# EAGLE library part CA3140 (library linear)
OP AMP

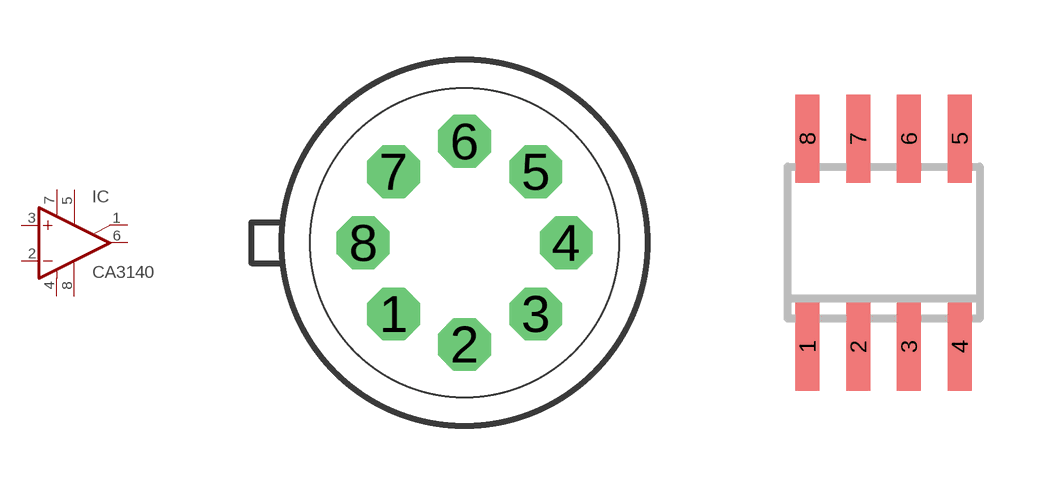
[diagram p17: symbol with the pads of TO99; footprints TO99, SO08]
Designator prefix IC

## CA3140T  [TO99]
1  ON/CMP  pas
2  -IN  in
3  +IN  in
4  V-  pwr
5  ON  pas
6  OUT  out
7  V+  pwr
8  CMP  pas

## CA3140D  [SO08]
Pads as for TO99

## CA3140N  [DIL08]
Pads as for TO99

## Footprint TO99 (pad centres in mm)
Metal Can Package
drill 0.813 octagon: 1 -1.778,-1.778; 2 0,-2.54; 3 1.778,-1.778; 4 2.54,0; 5 1.778,1.778; 6 0,2.54; 7 -1.778,1.778; 8 -2.54,0

## Footprint SO08 (pad centres in mm)
Small Outline Package 8 NS Package M08A
smd 0.6 x 2.2: 1 -1.905,-2.6; 2 -0.635,-2.6; 3 0.635,-2.6; 4 1.905,-2.6; 5 1.905,2.6; 6 0.635,2.6; 7 -0.635,2.6; 8 -1.905,2.6

## Footprint DIL08 (pad centres in mm)
Dual In Line Package
drill 0.813 pad 1.27 round: 1 -3.81,-3.81; 2 -1.27,-3.81; 3 1.27,-3.81; 4 3.81,-3.81; 5 3.81,3.81; 6 1.27,3.81; 7 -1.27,3.81; 8 -3.81,3.81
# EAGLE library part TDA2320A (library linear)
Power OP AMP

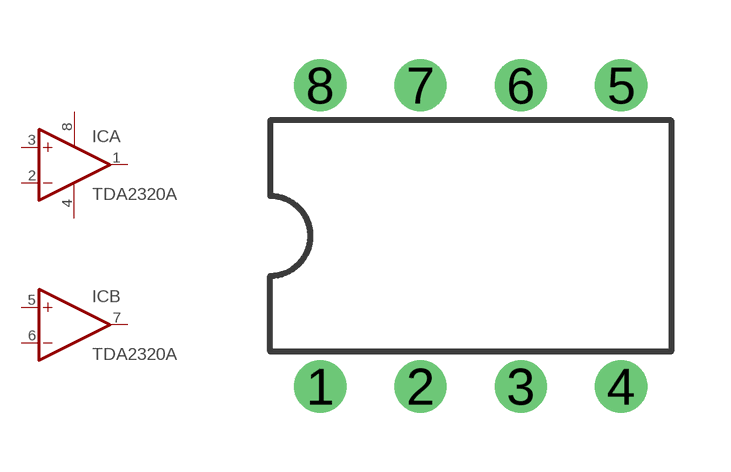
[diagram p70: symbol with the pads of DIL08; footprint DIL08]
Designator prefix IC; gates A=OPAMP B=OPAMP P=PWR+-

## TDA2320AP  [DIL08]
1  A:OUT  out
2  A:-IN  in
3  A:+IN  in
4  P:V-  pwr
5  B:+IN  in
6  B:-IN  in
7  B:OUT  out
8  P:V+  pwr

## Footprint DIL08 (pad centres in mm)
Dual In Line Package
drill 0.813 pad 1.27 round: 1 -3.81,-3.81; 2 -1.27,-3.81; 3 1.27,-3.81; 4 3.81,-3.81; 5 3.81,3.81; 6 1.27,3.81; 7 -1.27,3.81; 8 -3.81,3.81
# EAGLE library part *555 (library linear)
TIMER

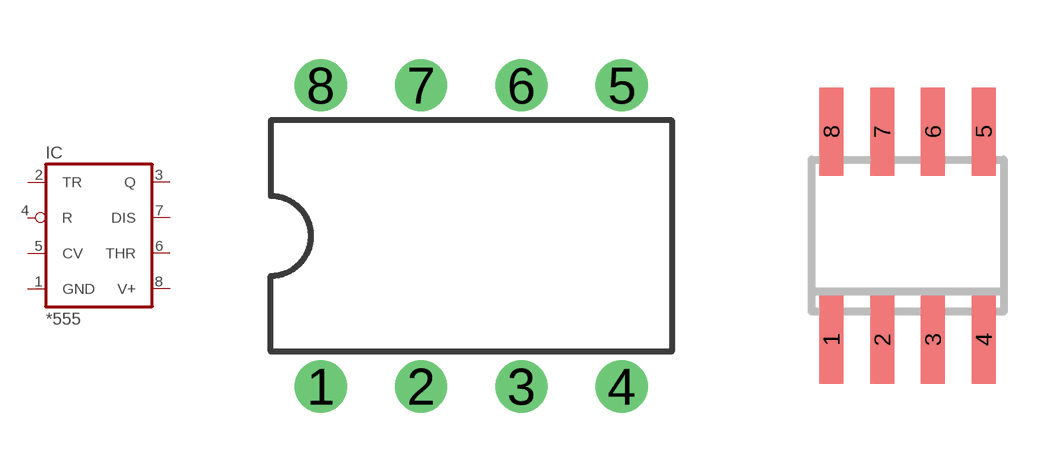
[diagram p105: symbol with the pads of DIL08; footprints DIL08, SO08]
Designator prefix IC

## LM555N, NE555N, SE555N, UA555N  [DIL08]
1  GND  pwr
2  TR  in
3  Q  out
4  R  in
5  CV  in
6  THR  in
7  DIS  in
8  V+  pwr

## LM555D, NE555D, SE555D, UA555D  [SO08]
Pads as for DIL08

## Footprint DIL08 (pad centres in mm)
Dual In Line Package
drill 0.813 pad 1.27 round: 1 -3.81,-3.81; 2 -1.27,-3.81; 3 1.27,-3.81; 4 3.81,-3.81; 5 3.81,3.81; 6 1.27,3.81; 7 -1.27,3.81; 8 -3.81,3.81

## Footprint SO08 (pad centres in mm)
Small Outline Package 8 NS Package M08A
smd 0.6 x 2.2: 1 -1.905,-2.6; 2 -0.635,-2.6; 3 0.635,-2.6; 4 1.905,-2.6; 5 1.905,2.6; 6 0.635,2.6; 7 -0.635,2.6; 8 -1.905,2.6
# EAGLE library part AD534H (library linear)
MULTIPLIER

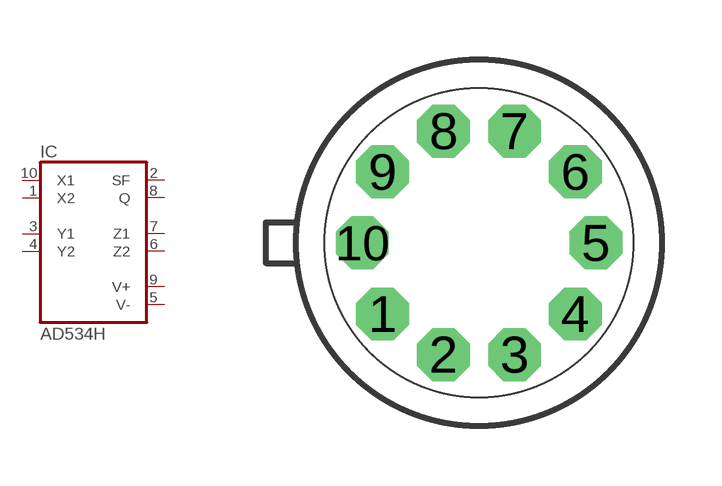
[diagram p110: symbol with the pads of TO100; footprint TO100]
Designator prefix IC

## AD534H  [TO100]
1  X2  in
2  SF  in
3  Y1  in
4  Y2  in
5  V-  pwr
6  Z2  in
7  Z1  in
8  Q  out
9  V+  pwr
10  X1  in

## Footprint TO100 (pad centres in mm)
Metal Can Package
drill 0.813 octagon: 1 -2.413,-1.778; 2 -0.889,-2.794; 3 0.889,-2.794; 4 2.413,-1.778; 5 2.921,0; 6 2.413,1.778; 7 0.889,2.794; 8 -0.889,2.794; 9 -2.413,1.778; 10 -2.921,0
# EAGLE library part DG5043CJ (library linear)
CMOS SWITCH

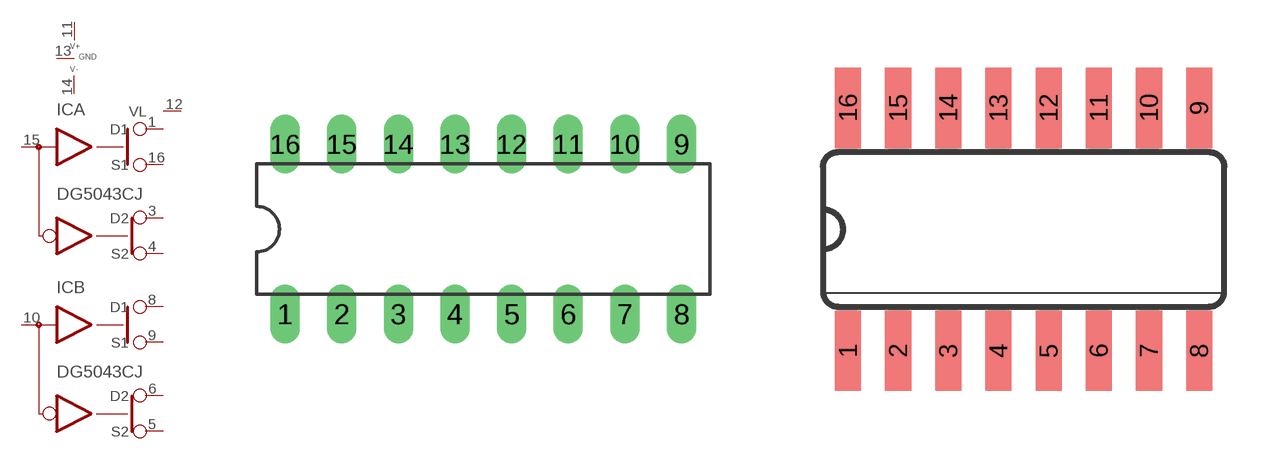
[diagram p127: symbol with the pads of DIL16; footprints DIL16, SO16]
Designator prefix IC; gates A=SWDPST B=SWDPST P=PWR+-GSS VL=VL_PIN

## DG5043CJN  [DIL16]
1  A:D1
3  A:D2
4  A:S2
5  B:S2
6  B:D2
8  B:D1
9  B:S1
10  B:IN  in
11  P:V+  pwr
12  VL:VL  in
13  P:GND  pwr
14  P:V-  pwr
15  A:IN  in
16  A:S1

## DG5043CJD  [SO16]
Pads as for DIL16

## Footprint DIL16 (pad centres in mm)
Dual In Line Package
drill 0.813 long: 1 -8.89,-3.81; 2 -6.35,-3.81; 3 -3.81,-3.81; 4 -1.27,-3.81; 5 1.27,-3.81; 6 3.81,-3.81; 7 6.35,-3.81; 8 8.89,-3.81; 9 8.89,3.81; 10 6.35,3.81; 11 3.81,3.81; 12 1.27,3.81; 13 -1.27,3.81; 14 -3.81,3.81; 15 -6.35,3.81; 16 -8.89,3.81

## Footprint SO16 (pad centres in mm)
Small Outline Package 16
smd 0.66 x 2.032: 1 -4.445,-3.073; 2 -3.175,-3.073; 3 -1.905,-3.073; 4 -0.635,-3.073; 5 0.635,-3.073; 6 1.905,-3.073; 7 3.175,-3.073; 8 4.445,-3.073; 9 4.445,3.073; 10 3.175,3.073; 11 1.905,3.073; 12 0.635,3.073; 13 -0.635,3.073; 14 -1.905,3.073; 15 -3.175,3.073; 16 -4.445,3.073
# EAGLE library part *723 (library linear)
Positive VOLTAGE REGULATOR

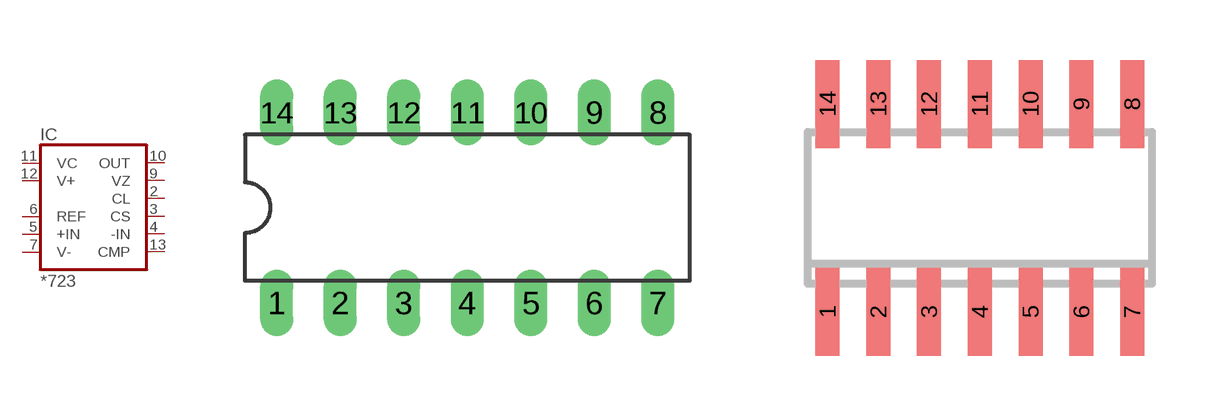
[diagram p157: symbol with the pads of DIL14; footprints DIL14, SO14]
Designator prefix IC

## LM723N, UA723N  [DIL14]
2  CL  in
3  CS  in
4  -IN  in
5  +IN  in
6  REF  out
7  V-  in
9  VZ  out
10  OUT  out
11  VC  in
12  V+  in
13  CMP  pas

## LM723D, UA723D  [SO14]
Pads as for DIL14

## Footprint DIL14 (pad centres in mm)
Dual In Line Package
drill 0.813 long: 1 -7.62,-3.81; 2 -5.08,-3.81; 3 -2.54,-3.81; 4 0,-3.81; 5 2.54,-3.81; 6 5.08,-3.81; 7 7.62,-3.81; 8 7.62,3.81; 9 5.08,3.81; 10 2.54,3.81; 11 0,3.81; 12 -2.54,3.81; 13 -5.08,3.81; 14 -7.62,3.81

## Footprint SO14 (pad centres in mm)
Small Outline Package 14
smd 0.6 x 2.2: 1 -3.81,-2.6; 2 -2.54,-2.6; 3 -1.27,-2.6; 4 0,-2.6; 5 1.27,-2.6; 6 2.54,-2.6; 7 3.81,-2.6; 8 3.81,2.6; 9 2.54,2.6; 10 1.27,2.6; 11 0,2.6; 12 -1.27,2.6; 13 -2.54,2.6; 14 -3.81,2.6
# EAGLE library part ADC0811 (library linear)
A/D CONVERTER with 10-channel multiplexer

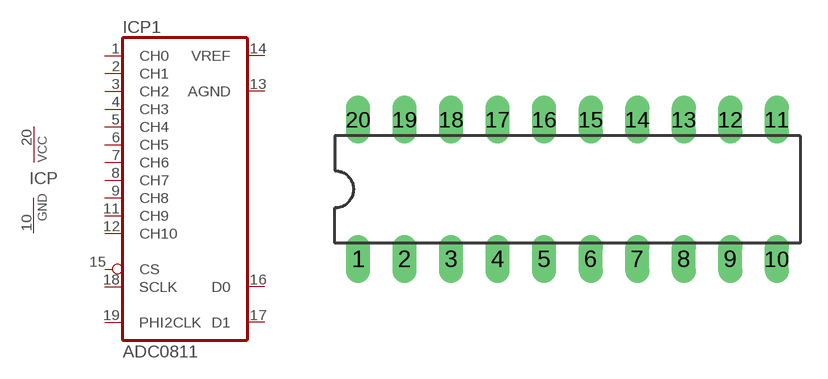
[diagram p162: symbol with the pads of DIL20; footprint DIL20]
Designator prefix IC; gates P1=ADC0811 P=PWRN

## ADC0811  [DIL20]
1  P1:CH0  in
2  P1:CH1  in
3  P1:CH2  in
4  P1:CH3  in
5  P1:CH4  in
6  P1:CH5  in
7  P1:CH6  in
8  P1:CH7  in
9  P1:CH8  in
10  P:GND  pwr
11  P1:CH9  in
12  P1:CH10  in
13  P1:AGND  in
14  P1:VREF  in
15  P1:CS  in
16  P1:D0  out
17  P1:D1  in
18  P1:SCLK  in
19  P1:PHI2CLK  in
20  P:VCC  pwr

## Footprint DIL20 (pad centres in mm)
Dual In Line Package
drill 0.813 long: 1 -11.43,-3.81; 2 -8.89,-3.81; 3 -6.35,-3.81; 4 -3.81,-3.81; 5 -1.27,-3.81; 6 1.27,-3.81; 7 3.81,-3.81; 8 6.35,-3.81; 9 8.89,-3.81; 10 11.43,-3.81; 11 11.43,3.81; 12 8.89,3.81; 13 6.35,3.81; 14 3.81,3.81; 15 1.27,3.81; 16 -1.27,3.81; 17 -3.81,3.81; 18 -6.35,3.81; 19 -8.89,3.81; 20 -11.43,3.81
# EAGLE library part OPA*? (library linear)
Ultra-Low Noise, Precision OP AMP Source: http://focus.ti.com/lit/ds/symlink/opa27.pdf http://focus.ti.com .. opa241.pdf

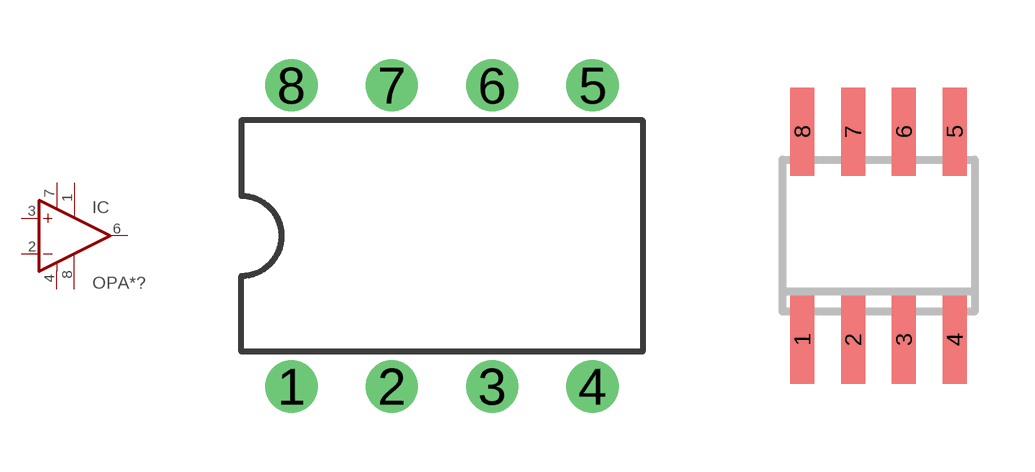
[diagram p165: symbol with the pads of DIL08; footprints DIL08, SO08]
Designator prefix IC

## OPA27GP, OPA37GP  [DIL08]
1  OFF1  pas
2  -IN  in
3  +IN  in
4  V-  pwr
6  OUT  out
7  V+  pwr
8  OFF2  pas

## OPA27U, OPA37U  [SO08]
Pads as for DIL08

## OPA241PA, OPA251PA  [DIL08]
Pads as for DIL08

## OPA241UA, OPA251UA  [SO08]
Pads as for DIL08

## Footprint DIL08 (pad centres in mm)
Dual In Line Package
drill 0.813 pad 1.27 round: 1 -3.81,-3.81; 2 -1.27,-3.81; 3 1.27,-3.81; 4 3.81,-3.81; 5 3.81,3.81; 6 1.27,3.81; 7 -1.27,3.81; 8 -3.81,3.81

## Footprint SO08 (pad centres in mm)
Small Outline Package 8 NS Package M08A
smd 0.6 x 2.2: 1 -1.905,-2.6; 2 -0.635,-2.6; 3 0.635,-2.6; 4 1.905,-2.6; 5 1.905,2.6; 6 0.635,2.6; 7 -0.635,2.6; 8 -1.905,2.6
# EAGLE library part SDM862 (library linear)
DATA ACQUSITION SYSTEM

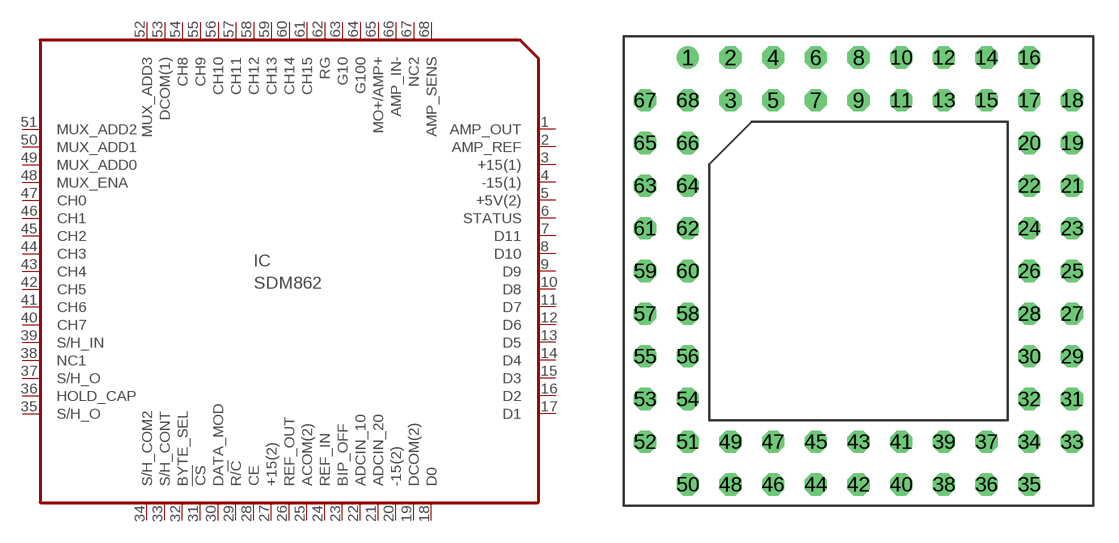
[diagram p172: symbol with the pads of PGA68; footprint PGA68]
Designator prefix IC

## SDM862  [PGA68]
1  AMP_OUT  out
2  AMP_REF  in
3  +15(1)  pwr
4  -15(1)  pwr
5  +5V(2)  pwr
6  STATUS  out
7  D11  hiz
8  D10  hiz
9  D9  hiz
10  D8  hiz
11  D7  hiz
12  D6  hiz
13  D5  hiz
14  D4  hiz
15  D3  hiz
16  D2  hiz
17  D1  hiz
18  D0  hiz
19  DCOM(2)  pwr
20  -15(2)  pwr
21  ADCIN_20  in
22  ADCIN_10  in
23  BIP_OFF  in
24  REF_IN  in
25  ACOM(2)  pwr
26  REF_OUT  out
27  +15(2)  pwr
28  CE  in
29  R/!C  in
30  DATA_MOD  in
31  !CS  in
32  BYTE_SEL  in
33  S/H_CONT  in
34  S/H_COM2
35  S/H_O  out
36  HOLD_CAP  pas
37  S/H_O  out
38  NC1  nc
39  S/H_IN  in
40  CH7  in
41  CH6  in
42  CH5  in
43  CH4  in
44  CH3  in
45  CH2  in
46  CH1  in
47  CH0  in
48  MUX_ENA  in
49  MUX_ADD0  in
50  MUX_ADD1  in
51  MUX_ADD2  in
52  MUX_ADD3  in
53  DCOM(1)  pwr
54  CH8  in
55  CH9  in
56  CH10  in
57  CH11  in
58  CH12  in
59  CH13  in
60  CH14  in
61  CH15  in
62  RG  pas
63  G10  pas
64  G100  pas
65  MO+/AMP+
66  AMP_IN-  in
67  NC2  nc
68  AMP_SENS  out

## Footprint PGA68 (pad centres in mm)
Pin Grid Array 68 lead
drill 0.813 round: 1 -10.16,12.7
drill 0.813 octagon: 2 -7.62,12.7; 3 -7.62,10.16; 4 -5.08,12.7; 5 -5.08,10.16; 6 -2.54,12.7; 7 -2.54,10.16; 8 0,12.7; 9 0,10.16; 10 2.54,12.7; 11 2.54,10.16; 12 5.08,12.7; 13 5.08,10.16; 14 7.62,12.7; 15 7.62,10.16; 16 10.16,12.7; 17 10.16,10.16; 18 12.7,10.16; 19 12.7,7.62; 20 10.16,7.62; 21 12.7,5.08; 22 10.16,5.08; 23 12.7,2.54; 24 10.16,2.54; 25 12.7,0; 26 10.16,0; 27 12.7,-2.54; 28 10.16,-2.54; 29 12.7,-5.08; 30 10.16,-5.08; 31 12.7,-7.62; 32 10.16,-7.62; 33 12.7,-10.16; 34 10.16,-10.16; 35 10.16,-12.7; 36 7.62,-12.7; 37 7.62,-10.16; 38 5.08,-12.7; 39 5.08,-10.16; 40 2.54,-12.7; 41 2.54,-10.16; 42 0,-12.7; 43 0,-10.16; 44 -2.54,-12.7; 45 -2.54,-10.16; 46 -5.08,-12.7; 47 -5.08,-10.16; 48 -7.62,-12.7; 49 -7.62,-10.16; 50 -10.16,-12.7; 51 -10.16,-10.16; 52 -12.7,-10.16; 53 -12.7,-7.62; 54 -10.16,-7.62; 55 -12.7,-5.08; 56 -10.16,-5.08; 57 -12.7,-2.54; 58 -10.16,-2.54; 59 -12.7,0; 60 -10.16,0; 61 -12.7,2.54; 62 -10.16,2.54; 63 -12.7,5.08; 64 -10.16,5.08; 65 -12.7,7.62; 66 -10.16,7.62; 67 -12.7,10.16; 68 -10.16,10.16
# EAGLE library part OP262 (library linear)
OP AMP

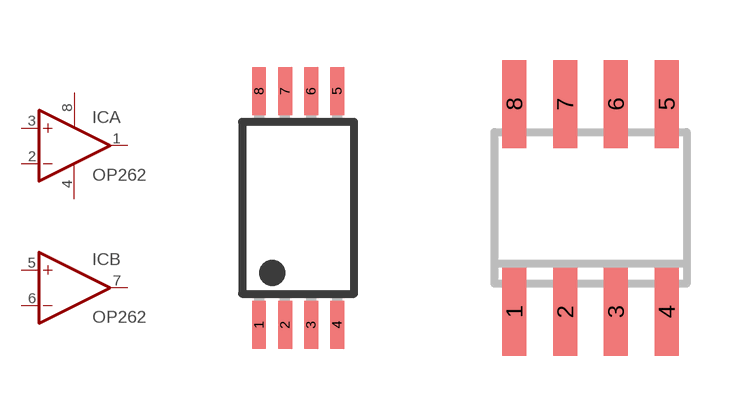
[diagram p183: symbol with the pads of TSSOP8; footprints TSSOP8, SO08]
Designator prefix IC; gates A=OPAMP B=OPAMP P=PWR+-

## OP262HRU  [TSSOP8]
1  A:OUT  out
2  A:-IN  in
3  A:+IN  in
4  P:V-  pwr
5  B:+IN  in
6  B:-IN  in
7  B:OUT  out
8  P:V+  pwr

## OP262D  [SO08]
Pads as for TSSOP8

## Footprint TSSOP8 (pad centres in mm)
Thin Shrink Small Outline Plastic 8 3 x 4.4 mm
smd 0.35 x 1.2: 1 -0.975,-2.925; 2 -0.325,-2.925; 3 0.325,-2.925; 4 0.975,-2.925; 5 0.975,2.925; 6 0.325,2.925; 7 -0.325,2.925; 8 -0.975,2.925

## Footprint SO08 (pad centres in mm)
Small Outline Package 8 NS Package M08A
smd 0.6 x 2.2: 1 -1.905,-2.6; 2 -0.635,-2.6; 3 0.635,-2.6; 4 1.905,-2.6; 5 1.905,2.6; 6 0.635,2.6; 7 -0.635,2.6; 8 -1.905,2.6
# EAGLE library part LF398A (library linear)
SAMPLE&HOLD AMPLIFIER

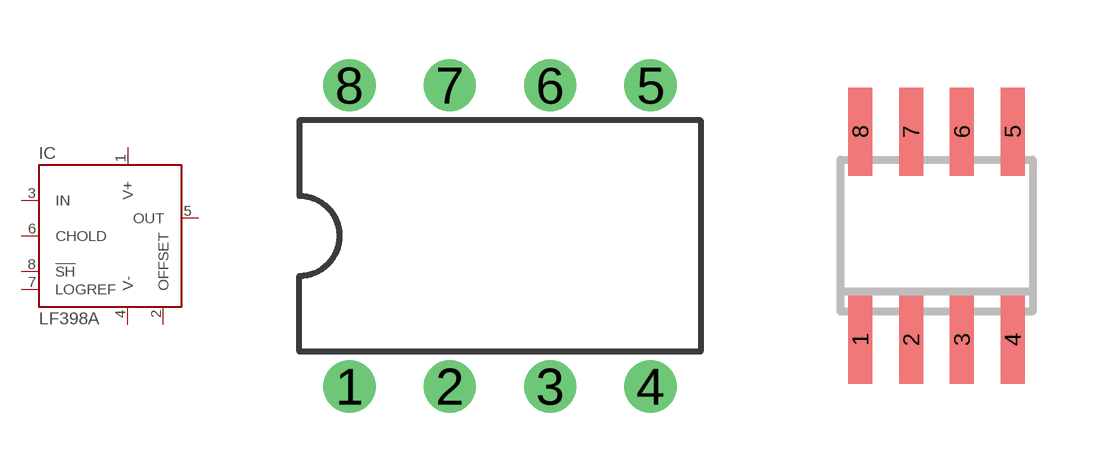
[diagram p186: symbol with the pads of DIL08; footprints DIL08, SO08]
Designator prefix IC

## LF398AN  [DIL08]
1  V+  pwr
2  OFFSET  in
3  IN  in
4  V-  pwr
5  OUT  out
6  CHOLD  pas
7  LOGREF  pwr
8  !SH  in

## LF398AD  [SO08]
Pads as for DIL08

## Footprint DIL08 (pad centres in mm)
Dual In Line Package
drill 0.813 pad 1.27 round: 1 -3.81,-3.81; 2 -1.27,-3.81; 3 1.27,-3.81; 4 3.81,-3.81; 5 3.81,3.81; 6 1.27,3.81; 7 -1.27,3.81; 8 -3.81,3.81

## Footprint SO08 (pad centres in mm)
Small Outline Package 8 NS Package M08A
smd 0.6 x 2.2: 1 -1.905,-2.6; 2 -0.635,-2.6; 3 0.635,-2.6; 4 1.905,-2.6; 5 1.905,2.6; 6 0.635,2.6; 7 -0.635,2.6; 8 -1.905,2.6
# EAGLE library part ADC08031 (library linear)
A/D CONVERTER

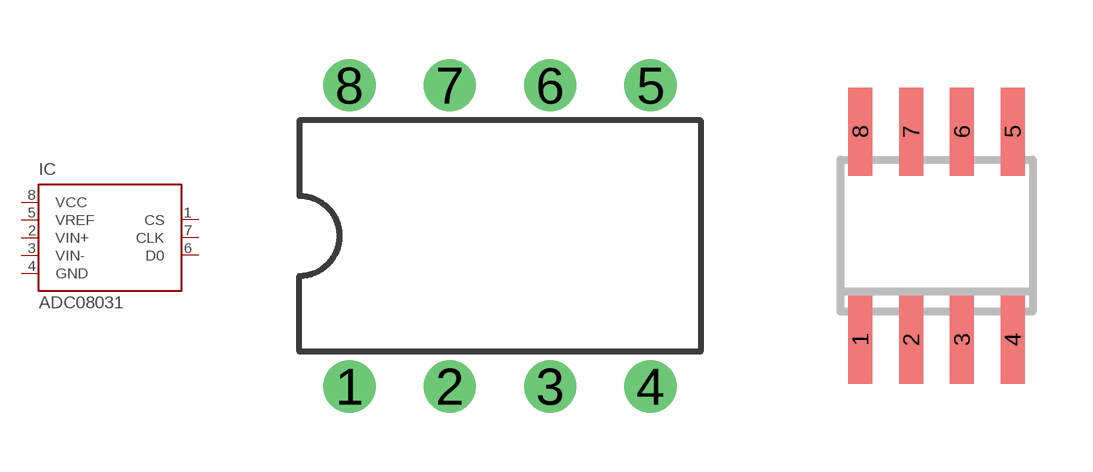
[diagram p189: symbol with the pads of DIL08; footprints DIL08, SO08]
Designator prefix IC

## ADC08031N  [DIL08]
1  CS  in
2  VIN+  in
3  VIN-  in
4  GND  pwr
5  VREF  in
6  D0  hiz
7  CLK  in
8  VCC  pwr

## ADC08031D  [SO08]
Pads as for DIL08

## Footprint DIL08 (pad centres in mm)
Dual In Line Package
drill 0.813 pad 1.27 round: 1 -3.81,-3.81; 2 -1.27,-3.81; 3 1.27,-3.81; 4 3.81,-3.81; 5 3.81,3.81; 6 1.27,3.81; 7 -1.27,3.81; 8 -3.81,3.81

## Footprint SO08 (pad centres in mm)
Small Outline Package 8 NS Package M08A
smd 0.6 x 2.2: 1 -1.905,-2.6; 2 -0.635,-2.6; 3 0.635,-2.6; 4 1.905,-2.6; 5 1.905,2.6; 6 0.635,2.6; 7 -0.635,2.6; 8 -1.905,2.6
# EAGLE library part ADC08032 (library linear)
A/D CONVERTER

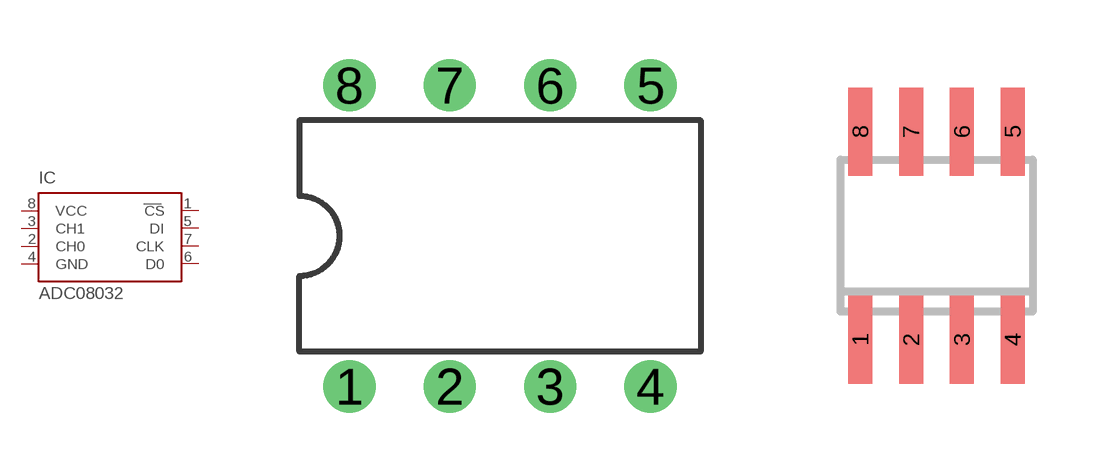
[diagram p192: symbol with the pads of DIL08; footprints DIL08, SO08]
Designator prefix IC

## ADC08032N  [DIL08]
1  CS  in
2  CH0  in
3  CH1  in
4  GND  pwr
5  DI  in
6  D0  hiz
7  CLK  in
8  VCC  pwr

## ADC08032D  [SO08]
Pads as for DIL08

## ADC08032S  [SO14W]
1  CS  in
3  CH0  in
5  CH1  in
7  GND  pwr
8  DI  in
10  D0  hiz
12  CLK  in
14  VCC  pwr

## Footprint DIL08 (pad centres in mm)
Dual In Line Package
drill 0.813 pad 1.27 round: 1 -3.81,-3.81; 2 -1.27,-3.81; 3 1.27,-3.81; 4 3.81,-3.81; 5 3.81,3.81; 6 1.27,3.81; 7 -1.27,3.81; 8 -3.81,3.81

## Footprint SO08 (pad centres in mm)
Small Outline Package 8 NS Package M08A
smd 0.6 x 2.2: 1 -1.905,-2.6; 2 -0.635,-2.6; 3 0.635,-2.6; 4 1.905,-2.6; 5 1.905,2.6; 6 0.635,2.6; 7 -0.635,2.6; 8 -1.905,2.6

## Footprint SO14W (pad centres in mm)
Small Outline Package 14 wide
smd 0.6 x 2.2: 1 -3.81,-4.6; 2 -2.54,-4.6; 3 -1.27,-4.6; 4 0,-4.6; 5 1.27,-4.6; 6 2.54,-4.6; 7 3.81,-4.6; 8 3.81,4.6; 9 2.54,4.6; 10 1.27,4.6; 11 0,4.6; 12 -1.27,4.6; 13 -2.54,4.6; 14 -3.81,4.6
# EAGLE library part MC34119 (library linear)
Low Power Audio Amplifier Motorola

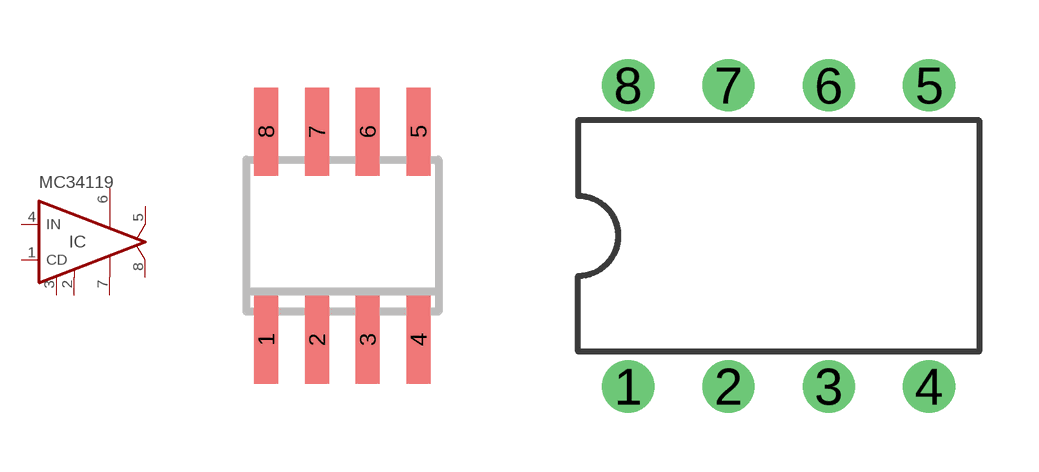
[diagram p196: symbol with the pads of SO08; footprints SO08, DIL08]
Designator prefix IC

## MC34119D  [SO08]
1  CD  pas
2  FC2  pas
3  FC1  pas
4  IN  in
5  VO1  out
6  VCC  pwr
7  GND  pwr
8  VO2  out

## MC34119P  [DIL08]
Pads as for SO08

## MC34119DTB  [TSSOP8]
Pads as for SO08

## Footprint SO08 (pad centres in mm)
Small Outline Package 8 NS Package M08A
smd 0.6 x 2.2: 1 -1.905,-2.6; 2 -0.635,-2.6; 3 0.635,-2.6; 4 1.905,-2.6; 5 1.905,2.6; 6 0.635,2.6; 7 -0.635,2.6; 8 -1.905,2.6

## Footprint DIL08 (pad centres in mm)
Dual In Line Package
drill 0.813 pad 1.27 round: 1 -3.81,-3.81; 2 -1.27,-3.81; 3 1.27,-3.81; 4 3.81,-3.81; 5 3.81,3.81; 6 1.27,3.81; 7 -1.27,3.81; 8 -3.81,3.81

## Footprint TSSOP8 (pad centres in mm)
Thin Shrink Small Outline Plastic 8 3 x 4.4 mm
smd 0.35 x 1.2: 1 -0.975,-2.925; 2 -0.325,-2.925; 3 0.325,-2.925; 4 0.975,-2.925; 5 0.975,2.925; 6 0.325,2.925; 7 -0.325,2.925; 8 -0.975,2.925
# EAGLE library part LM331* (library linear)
Simple Stand-Alone Voltage-to-Frequency Converter LM231 with ±0.03% Typical Linearity (f = 10 Hz to 11 kHz)

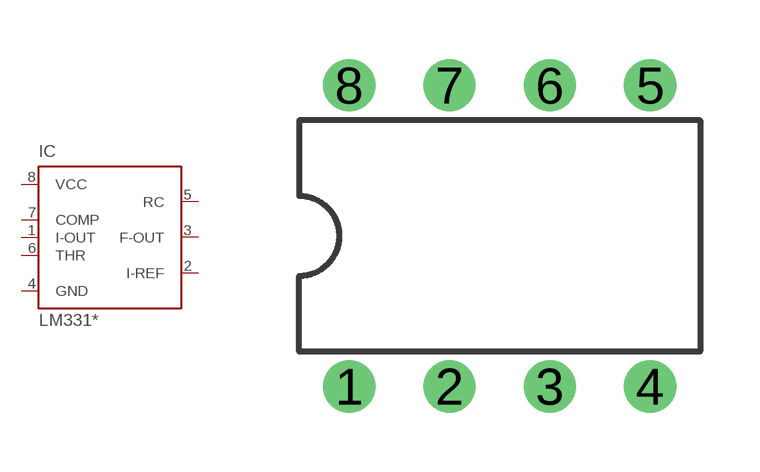
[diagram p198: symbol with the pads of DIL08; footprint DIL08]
Designator prefix IC

## LM331N, LM331AN  [DIL08]
1  I-OUT  out
2  I-REF  pas
3  F-OUT  oc
4  GND  pwr
5  RC  pas
6  THR  in
7  COMP  in
8  VCC  pwr

## Footprint DIL08 (pad centres in mm)
Dual In Line Package
drill 0.813 pad 1.27 round: 1 -3.81,-3.81; 2 -1.27,-3.81; 3 1.27,-3.81; 4 3.81,-3.81; 5 3.81,3.81; 6 1.27,3.81; 7 -1.27,3.81; 8 -3.81,3.81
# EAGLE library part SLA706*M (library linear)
UNIPOLAR STEPPER-MOTOR TRANSLATOR/DRIVERS Source: www.allegromicro.com .. 97060.pdf

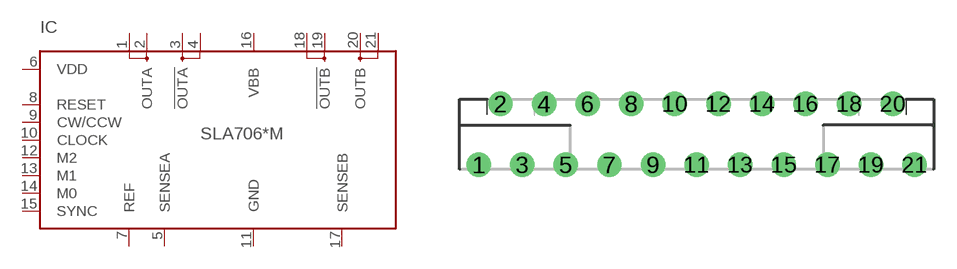
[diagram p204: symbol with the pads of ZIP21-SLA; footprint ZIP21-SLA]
Designator prefix IC

## SLA7060M, SLA7061M, SLA7062M  [ZIP21-SLA]
1  OUTA  pas
2  OUTA  out
3  !OUTA  out
4  !OUTA  pas
5  SENSEA  in
6  VDD  pwr
7  REF  in
8  RESET  in
9  CW/CCW  in
10  CLOCK  in
11  GND  pwr
12  M2  in
13  M1  in
14  M0  in
15  SYNC  in
16  VBB  pwr
17  SENSEB  in
18  !OUTB  pas
19  !OUTB  out
20  OUTB  out
21  OUTB  pas

## Footprint ZIP21-SLA (pad centres in mm)
Small molded power package ZIP-type 21-pin SLA package Source: www.allegromicro.com .. 97060.pdf
drill 0.8 pad 1.6 round: 1 -14.3,-2; 2 -12.87,2; 3 -11.44,-2; 4 -10.01,2; 5 -8.58,-2; 6 -7.15,2; 7 -5.72,-2; 8 -4.29,2; 9 -2.86,-2; 10 -1.43,2; 11 0,-2; 12 1.43,2; 13 2.86,-2; 14 4.29,2; 15 5.72,-2; 16 7.15,2; 17 8.58,-2; 18 10.01,2; 19 11.44,-2; 20 12.87,2; 21 14.3,-2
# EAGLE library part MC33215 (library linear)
Telefon Line Interface and Speakerphone Circuit Source: www.motorola.com .. MC33215.pdf

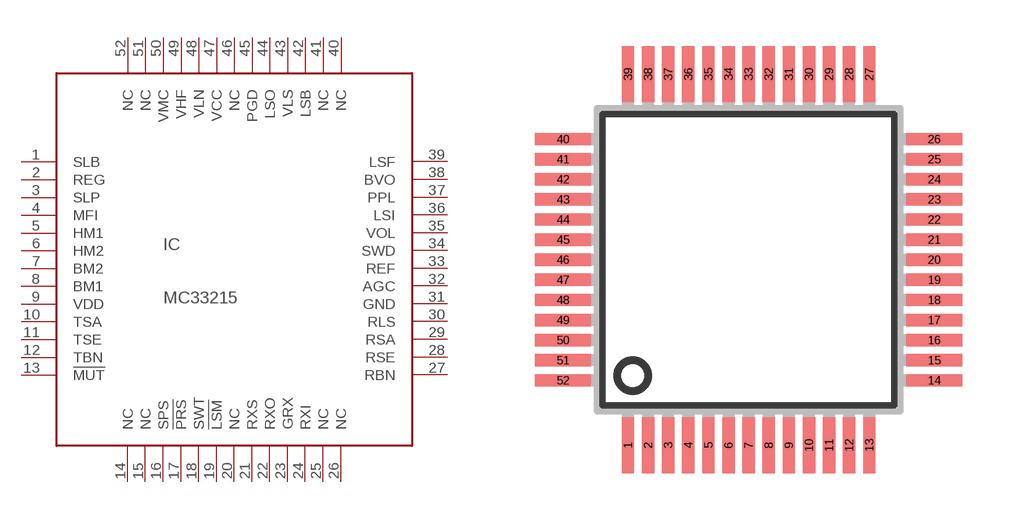
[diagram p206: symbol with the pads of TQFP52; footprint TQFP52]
Designator prefix IC

## MC33215FB  [TQFP52]
1  SLB  in
2  REG  in
3  SLP  in
4  MFI  in
5  HM1  in
6  HM2  in
7  BM2  in
8  BM1  in
9  VDD  in
10  TSA  in
11  TSE  in
12  TBN  in
13  !MUT  in
14  NC  in
15  NC  in
16  SPS  in
17  !PRS  in
18  SWT  in
19  !LSM  in
20  NC  in
21  RXS  in
22  RXO  in
23  GRX  in
24  RXI  in
25  NC  in
26  NC  in
27  RBN  in
28  RSE  in
29  RSA  in
30  RLS  in
31  GND  in
32  AGC  in
33  REF  in
34  SWD  in
35  VOL  in
36  LSI  in
37  PPL  in
38  BVO  in
39  LSF  in
40  NC  in
41  NC  in
42  LSB  in
43  VLS  in
44  LSO  in
45  PGD  in
46  NC  in
47  VCC  in
48  VLN  in
49  VHF  in
50  VMC  in
51  NC  in
52  NC  in

## Footprint TQFP52 (pad centres in mm)
TQFP-52 PLASTIC PACKAGE CASE 848B-04 Source: www.motorola.com .. MC33215.pdf
smd 0.4 x 1.8: 1 -3.9,-6; 2 -3.25,-6; 3 -2.6,-6; 4 -1.95,-6; 5 -1.3,-6; 6 -0.65,-6; 7 0,-6; 8 0.65,-6; 9 1.3,-6; 10 1.95,-6; 11 2.6,-6; 12 3.25,-6; 13 3.9,-6; 27 3.9,6; 28 3.25,6; 29 2.6,6; 30 1.95,6; 31 1.3,6; 32 0.65,6; 33 0,6; 34 -0.65,6; 35 -1.3,6; 36 -1.95,6; 37 -2.6,6; 38 -3.25,6; 39 -3.9,6
smd 1.8 x 0.4: 14 6,-3.9; 15 6,-3.25; 16 6,-2.6; 17 6,-1.95; 18 6,-1.3; 19 6,-0.65; 20 6,0; 21 6,0.65; 22 6,1.3; 23 6,1.95; 24 6,2.6; 25 6,3.25; 26 6,3.9; 40 -6,3.9; 41 -6,3.25; 42 -6,2.6; 43 -6,1.95; 44 -6,1.3; 45 -6,0.65; 46 -6,0; 47 -6,-0.65; 48 -6,-1.3; 49 -6,-1.95; 50 -6,-2.6; 51 -6,-3.25; 52 -6,-3.9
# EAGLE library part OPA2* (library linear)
Dual Operational Amplifier Low Power, Single-Supply, Rail-To-Rail Operational Amplifier Source: http://focus.ti.com/lit/ds/symlink/opa2345.pdf http://focus.ti.com .. opa241.pdf http://focus.ti.com/lit/ds/symlink/opa2134.pdf

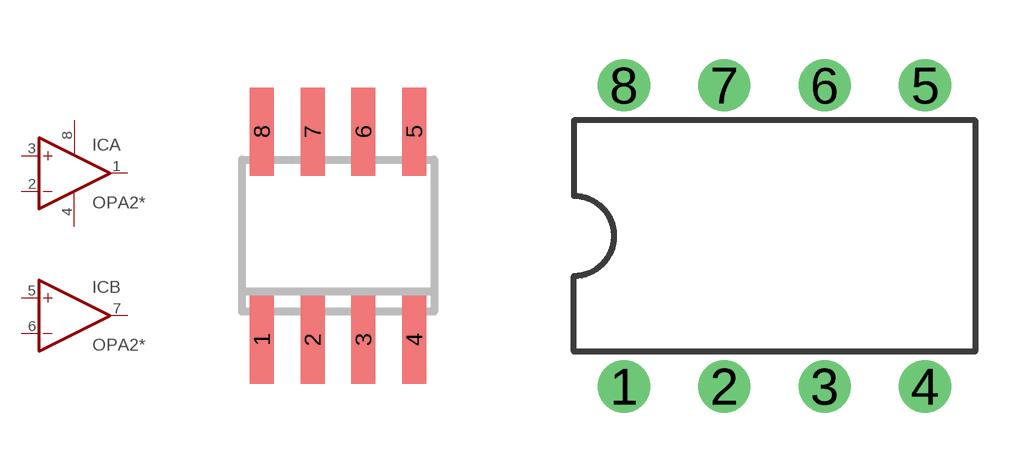
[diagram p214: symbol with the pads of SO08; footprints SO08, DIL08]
Designator prefix IC; gates A=OPAMP+- B=OPAMP

## OPA2344U, OPA2345U  [SO08]
1  A:OUT  out
2  A:-IN  in
3  A:+IN  in
4  A:V-  pwr
5  B:+IN  in
6  B:-IN  in
7  B:OUT  out
8  A:V+  pwr

## OPA2344P  [DIL08]
Pads as for SO08

## OPA2344E, OPA2345E  [MSOP08]
Pads as for SO08

## OPA2134PA, OPA2241PA, OPA2251PA  [DIL08]
Pads as for SO08

## OPA2134UA, OPA2241UA, OPA2251UA  [SO08]
Pads as for SO08

## Footprint SO08 (pad centres in mm)
Small Outline Package 8 NS Package M08A
smd 0.6 x 2.2: 1 -1.905,-2.6; 2 -0.635,-2.6; 3 0.635,-2.6; 4 1.905,-2.6; 5 1.905,2.6; 6 0.635,2.6; 7 -0.635,2.6; 8 -1.905,2.6

## Footprint DIL08 (pad centres in mm)
Dual In Line Package
drill 0.813 pad 1.27 round: 1 -3.81,-3.81; 2 -1.27,-3.81; 3 1.27,-3.81; 4 3.81,-3.81; 5 3.81,3.81; 6 1.27,3.81; 7 -1.27,3.81; 8 -3.81,3.81

## Footprint MSOP08 (pad centres in mm)
Mini Small Outline Package
smd 0.3 x 1.2: 1 -0.976,-2.113; 2 -0.326,-2.113; 3 0.324,-2.113; 4 0.974,-2.113; 5 0.974,2.112; 6 0.324,2.112; 7 -0.326,2.112; 8 -0.976,2.112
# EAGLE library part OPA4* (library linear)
Quad Operational Amplifier compatible with: TLC27L4 Low Power, Single-Supply, Rail-To-Rail Operational Amplifier Source: http://focus.ti.com/lit/ds/symlink/opa2345.pdf http://focus.ti.com .. opa241.pdf http://focus.ti.com .. tlc27l4.pdf http://focus.ti.com/lit/ds/symlink/opa2134.pdf

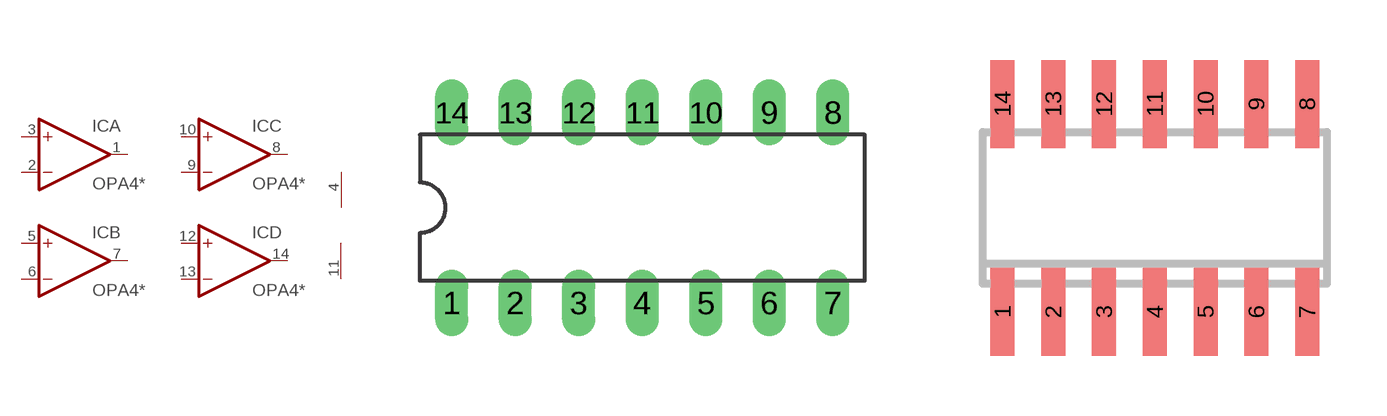
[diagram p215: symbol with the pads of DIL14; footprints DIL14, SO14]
Designator prefix IC; gates A=OPAMP B=OPAMP C=OPAMP D=OPAMP P=PWR+-

## OPA4344P  [DIL14]
1  A:OUT  out
2  A:-IN  in
3  A:+IN  in
4  P:V+  pwr
5  B:+IN  in
6  B:-IN  in
7  B:OUT  out
8  C:OUT  out
9  C:-IN  in
10  C:+IN  in
11  P:V-  pwr
12  D:+IN  in
13  D:-IN  in
14  D:OUT  out

## OPA4344U, OPA4345U  [SO14]
Pads as for DIL14

## OPA4344E, OPA4345E  [TSSOP14]
Pads as for DIL14

## OPA4134PA, OPA4241PA, OPA4251PA  [DIL14]
Pads as for DIL14

## OPA4134UA, OPA4241UA, OPA4251UA  [SO14]
Pads as for DIL14

## Footprint DIL14 (pad centres in mm)
Dual In Line Package
drill 0.813 long: 1 -7.62,-3.81; 2 -5.08,-3.81; 3 -2.54,-3.81; 4 0,-3.81; 5 2.54,-3.81; 6 5.08,-3.81; 7 7.62,-3.81; 8 7.62,3.81; 9 5.08,3.81; 10 2.54,3.81; 11 0,3.81; 12 -2.54,3.81; 13 -5.08,3.81; 14 -7.62,3.81

## Footprint SO14 (pad centres in mm)
Small Outline Package 14
smd 0.6 x 2.2: 1 -3.81,-2.6; 2 -2.54,-2.6; 3 -1.27,-2.6; 4 0,-2.6; 5 1.27,-2.6; 6 2.54,-2.6; 7 3.81,-2.6; 8 3.81,2.6; 9 2.54,2.6; 10 1.27,2.6; 11 0,2.6; 12 -1.27,2.6; 13 -2.54,2.6; 14 -3.81,2.6

## Footprint TSSOP14 (pad centres in mm)
Thin Shrink Small Outline Plastic 14
smd 0.305 x 0.991: 1 -1.905,-2.718; 2 -1.27,-2.718; 3 -0.635,-2.718; 4 0,-2.718; 5 0.635,-2.718; 6 1.27,-2.718; 7 1.905,-2.718; 8 1.905,2.718; 9 1.27,2.718; 10 0.635,2.718; 11 0,2.718; 12 -0.635,2.718; 13 -1.27,2.718; 14 -1.905,2.718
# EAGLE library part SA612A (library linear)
Double-balanced mixer and oscillator NE612/SA612 Source: www-eu2.semiconductors.philips.com/acrobat/datasheets/SA612A.pdf

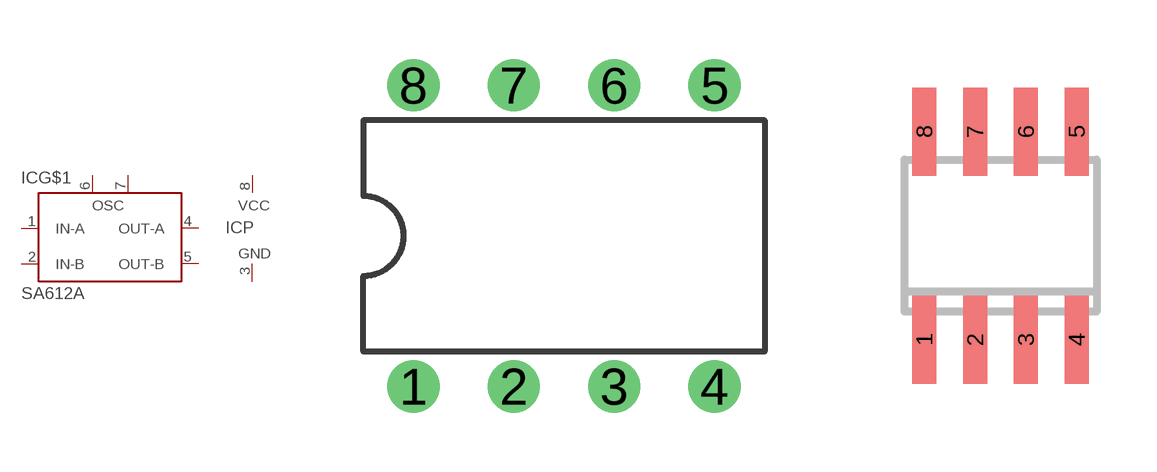
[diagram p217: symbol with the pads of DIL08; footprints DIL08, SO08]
Designator prefix IC; gates G$1=SA612A P=VCCGND

## SA612AN  [DIL08]
1  G$1:IN-A  in
2  G$1:IN-B  in
3  P:GND  pwr
4  G$1:OUT-A  in
5  G$1:OUT-B  in
6  G$1:OSC  pas
7  G$1:OSC'  pas
8  P:VCC  pwr

## SA612AD  [SO08]
Pads as for DIL08

## Footprint DIL08 (pad centres in mm)
Dual In Line Package
drill 0.813 pad 1.27 round: 1 -3.81,-3.81; 2 -1.27,-3.81; 3 1.27,-3.81; 4 3.81,-3.81; 5 3.81,3.81; 6 1.27,3.81; 7 -1.27,3.81; 8 -3.81,3.81

## Footprint SO08 (pad centres in mm)
Small Outline Package 8 NS Package M08A
smd 0.6 x 2.2: 1 -1.905,-2.6; 2 -0.635,-2.6; 3 0.635,-2.6; 4 1.905,-2.6; 5 1.905,2.6; 6 0.635,2.6; 7 -0.635,2.6; 8 -1.905,2.6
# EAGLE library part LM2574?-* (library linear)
SIMPLE SWITCHER 0.5A Step-Down Voltage Regulator Source: http://cache.national.com/ds/LM/LM2574.pdf

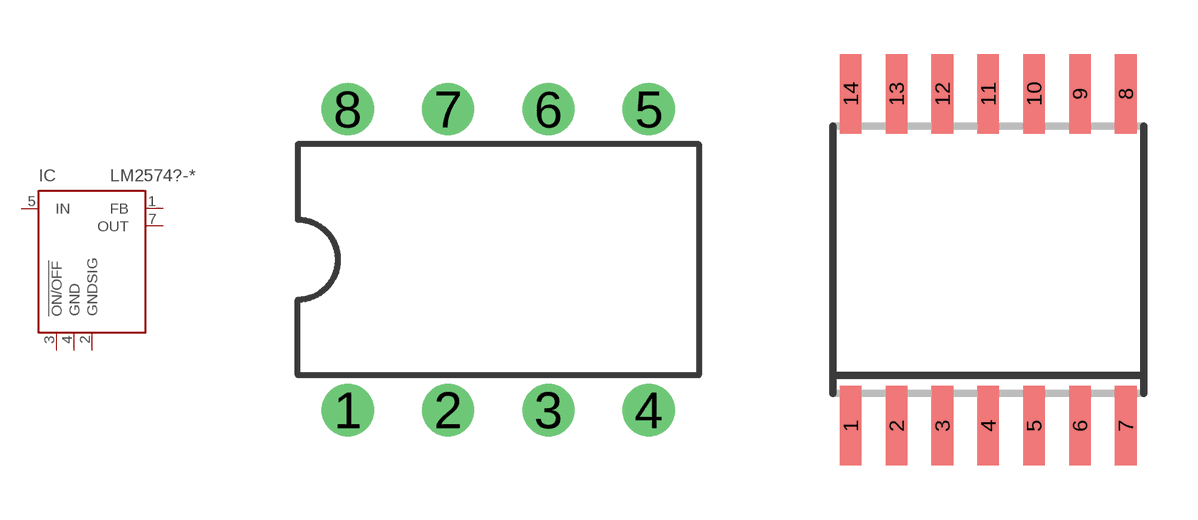
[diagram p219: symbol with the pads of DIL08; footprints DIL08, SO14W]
Designator prefix IC

## LM2574HVN-12, LM2574HVN-15, LM2574HVN-3.3, LM2574HVN-5.0, LM2574HVN-ADJ  [DIL08]
1  FB  in
2  GNDSIG  in
3  !ON/OFF  in
4  GND  pwr
5  IN  in
7  OUT  pas

## LM2574HVM-12, LM2574HVM-15, LM2574HVM-3.3, LM2574HVM-5.0, LM2574HVM-ADJ  [SO14W]
3  FB  in
4  GNDSIG  in
5  !ON/OFF  in
6  GND  pwr
10  IN  in
12  OUT  pas

## LM2574N-12, LM2574N-3.3, LM2574N-5.0, LM2574N-ADJ  [DIL08]
Pads as for DIL08

## LM2574M-12, LM2574M-15, LM2574M-3.3, LM2574M-5.0, LM2574M-ADJ  [SO14W]
Pads as for SO14W

## Footprint DIL08 (pad centres in mm)
Dual In Line Package
drill 0.813 pad 1.27 round: 1 -3.81,-3.81; 2 -1.27,-3.81; 3 1.27,-3.81; 4 3.81,-3.81; 5 3.81,3.81; 6 1.27,3.81; 7 -1.27,3.81; 8 -3.81,3.81

## Footprint SO14W (pad centres in mm)
Small Outline Package 14 wide
smd 0.6 x 2.2: 1 -3.81,-4.6; 2 -2.54,-4.6; 3 -1.27,-4.6; 4 0,-4.6; 5 1.27,-4.6; 6 2.54,-4.6; 7 3.81,-4.6; 8 3.81,4.6; 9 2.54,4.6; 10 1.27,4.6; 11 0,4.6; 12 -1.27,4.6; 13 -2.54,4.6; 14 -3.81,4.6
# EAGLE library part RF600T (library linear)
Smart Com Radio Transceiver IC Source: http://www.rfsolutions.co.uk/acatalog/DS601-4.pdf

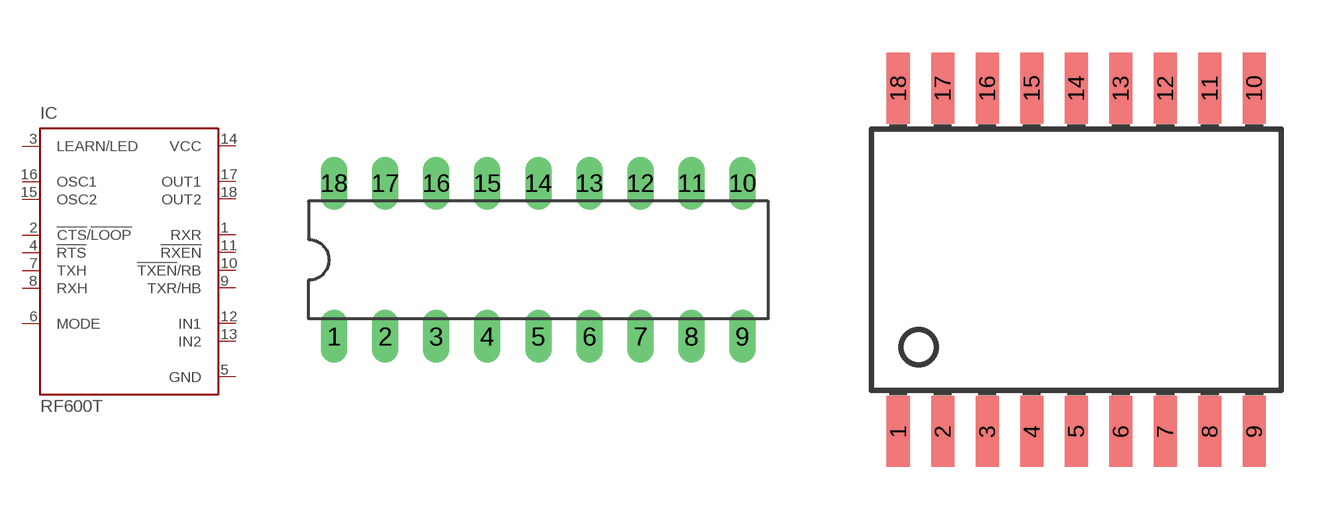
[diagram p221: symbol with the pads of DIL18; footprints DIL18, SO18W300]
Designator prefix IC

## RF600T  [DIL18]
1  RXR  in
2  !CTS!/!LOOP  in
3  LEARN/LED
4  !RTS  in
5  GND  in
6  MODE  in
7  TXH  in
8  RXH  out
9  TXR/HB
10  !TXEN!/RB
11  !RXEN  out
12  IN1  in
13  IN2  in
14  VCC  in
15  OSC2  out
16  OSC1  in
17  OUT1  out
18  OUT2  out

## RF600T-SO  [SO18W300]
Pads as for DIL18

## Footprint DIL18 (pad centres in mm)
Dual In Line Package
drill 0.813 long: 1 -10.16,-3.81; 2 -7.62,-3.81; 3 -5.08,-3.81; 4 -2.54,-3.81; 5 0,-3.81; 6 2.54,-3.81; 7 5.08,-3.81; 8 7.62,-3.81; 9 10.16,-3.81; 10 10.16,3.81; 11 7.62,3.81; 12 5.08,3.81; 13 2.54,3.81; 14 0,3.81; 15 -2.54,3.81; 16 -5.08,3.81; 17 -7.62,3.81; 18 -10.16,3.81

## Footprint SO18W300 (pad centres in mm)
18-Lead Plastic Small Outline (SO) - Wide, 300 mil (SOIC) Source: http://www.rfsolutions.co.uk/acatalog/DS601-4.pdf
smd 0.66 x 2.032: 1 -5.08,-4.902; 2 -3.81,-4.902; 3 -2.54,-4.902; 4 -1.27,-4.902; 5 0,-4.902; 6 1.27,-4.902; 7 2.54,-4.902; 8 3.81,-4.902; 9 5.08,-4.902; 10 5.08,4.902; 11 3.81,4.902; 12 2.54,4.902; 13 1.27,4.902; 14 0,4.902; 15 -1.27,4.902; 16 -2.54,4.902; 17 -3.81,4.902; 18 -5.08,4.902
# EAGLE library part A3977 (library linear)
MICROSTEPPING DMOS DRIVER WITH TRANSLATOR Source: http://allegromicro.com/datafile/3977.pdf

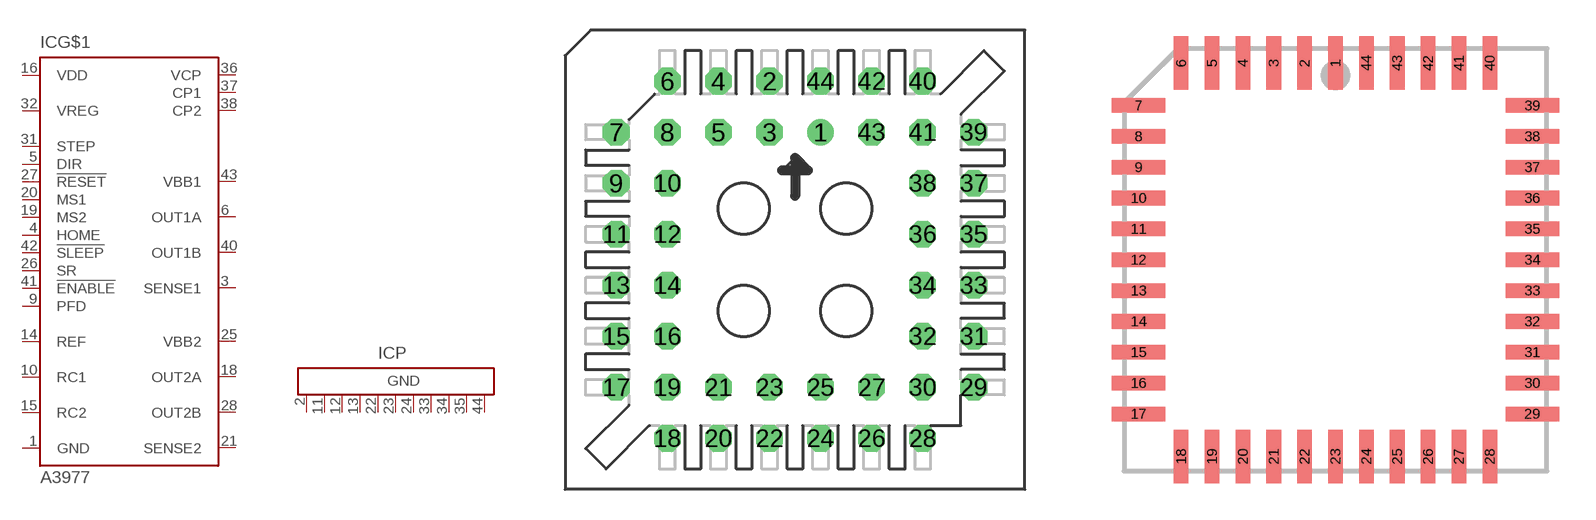
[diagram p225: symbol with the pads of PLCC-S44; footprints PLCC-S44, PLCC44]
Designator prefix IC; gates G$1=A3977 P=A3977PWR

## A3977SOCKED  [PLCC-S44]
1  G$1:GND  pwr
2  P:GND  pwr
3  G$1:SENSE1  in
4  G$1:HOME  in
5  G$1:DIR  in
6  G$1:OUT1A  out
9  G$1:PFD  in
10  G$1:RC1  pas
11  P:GND  pwr
12  P:GND  pwr
13  P:GND  pwr
14  G$1:REF  in
15  G$1:RC2  pas
16  G$1:VDD  pwr
18  G$1:OUT2A  out
19  G$1:MS2  in
20  G$1:MS1  in
21  G$1:SENSE2  in
22  P:GND  pwr
23  P:GND  pwr
24  P:GND  pwr
25  G$1:VBB2  pwr
26  G$1:SR  in
27  G$1:!RESET  in
28  G$1:OUT2B  out
31  G$1:STEP  in
32  G$1:VREG  pwr
33  P:GND  pwr
34  P:GND  pwr
35  P:GND  pwr
36  G$1:VCP  pas
37  G$1:CP1  pas
38  G$1:CP2  pas
40  G$1:OUT1B  out
41  G$1:!ENABLE  in
42  G$1:!SLEEP  in
43  G$1:VBB1  pwr
44  P:GND  pwr

## A3977  [PLCC44]
Pads as for PLCC-S44

## Footprint PLCC-S44 (pad centres in mm)
Plastic Leaded Chip Carrier Socked
drill 0.813 round: 1 1.27,6.35
drill 0.813 octagon: 2 -1.27,8.89; 3 -1.27,6.35; 4 -3.81,8.89; 5 -3.81,6.35; 6 -6.35,8.89; 7 -8.89,6.35; 8 -6.35,6.35; 9 -8.89,3.81; 10 -6.35,3.81; 11 -8.89,1.27; 12 -6.35,1.27; 13 -8.89,-1.27; 14 -6.35,-1.27; 15 -8.89,-3.81; 16 -6.35,-3.81; 17 -8.89,-6.35; 18 -6.35,-8.89; 19 -6.35,-6.35; 20 -3.81,-8.89; 21 -3.81,-6.35; 22 -1.27,-8.89; 23 -1.27,-6.35; 24 1.27,-8.89; 25 1.27,-6.35; 26 3.81,-8.89; 27 3.81,-6.35; 28 6.35,-8.89; 29 8.89,-6.35; 30 6.35,-6.35; 31 8.89,-3.81; 32 6.35,-3.81; 33 8.89,-1.27; 34 6.35,-1.27; 35 8.89,1.27; 36 6.35,1.27; 37 8.89,3.81; 38 6.35,3.81; 39 8.89,6.35; 40 6.35,8.89; 41 6.35,6.35; 42 3.81,8.89; 43 3.81,6.35; 44 1.27,8.89

## Footprint PLCC44 (pad centres in mm)
PLASTIC LEADED CHIP CARRIER square
smd 0.6 x 2.2: 1 0,8.1; 2 -1.27,8.1; 3 -2.54,8.1; 4 -3.81,8.1; 5 -5.08,8.1; 6 -6.35,8.1; 18 -6.35,-8.1; 19 -5.08,-8.1; 20 -3.81,-8.1; 21 -2.54,-8.1; 22 -1.27,-8.1; 23 0,-8.1; 24 1.27,-8.1; 25 2.54,-8.1; 26 3.81,-8.1; 27 5.08,-8.1; 28 6.35,-8.1; 40 6.35,8.1; 41 5.08,8.1; 42 3.81,8.1; 43 2.54,8.1; 44 1.27,8.1
smd 2.2 x 0.6: 7 -8.1,6.35; 8 -8.1,5.08; 9 -8.1,3.81; 10 -8.1,2.54; 11 -8.1,1.27; 12 -8.1,0; 13 -8.1,-1.27; 14 -8.1,-2.54; 15 -8.1,-3.81; 16 -8.1,-5.08; 17 -8.1,-6.35; 29 8.1,-6.35; 30 8.1,-5.08; 31 8.1,-3.81; 32 8.1,-2.54; 33 8.1,-1.27; 34 8.1,0; 35 8.1,1.27; 36 8.1,2.54; 37 8.1,3.81; 38 8.1,5.08; 39 8.1,6.35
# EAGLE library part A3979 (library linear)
Microstepping DMOS Driver with Translator Source: http://allegromicro.com/datafile/3979.pdf

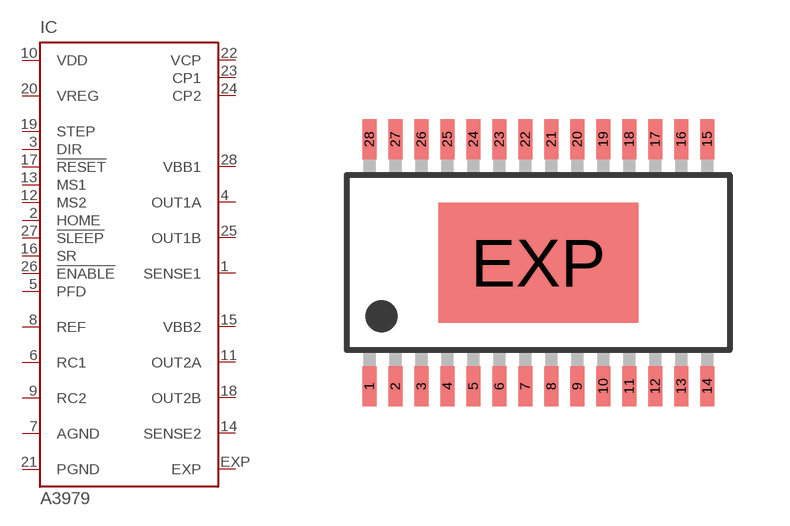
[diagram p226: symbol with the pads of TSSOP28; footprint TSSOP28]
Designator prefix IC

## A3979  [TSSOP28]
1  SENSE1  in
2  HOME  in
3  DIR  in
4  OUT1A  out
5  PFD  in
6  RC1  pas
7  AGND  pwr
8  REF  in
9  RC2  pas
10  VDD  pwr
11  OUT2A  out
12  MS2  in
13  MS1  in
14  SENSE2  in
15  VBB2  pwr
16  SR  in
17  !RESET  in
18  OUT2B  out
19  STEP  in
20  VREG  pwr
21  PGND  pwr
22  VCP  pas
23  CP1  pas
24  CP2  pas
25  OUT1B  out
26  !ENABLE  in
27  !SLEEP  in
28  VBB1  pwr
EXP  EXP  pwr

## Footprint TSSOP28 (pad centres in mm)
LP Package, 28-Pin TSSOP with Exposed Thermal Pad Source: http://allegromicro.com/datafile/3979.pdf
smd 0.35 x 1: 1 -4.225,-3.087; 2 -3.575,-3.087; 3 -2.925,-3.087; 4 -2.275,-3.087; 5 -1.625,-3.087; 6 -0.975,-3.087; 7 -0.325,-3.087; 8 0.325,-3.087; 9 0.975,-3.087; 10 1.625,-3.087; 11 2.275,-3.087; 12 2.925,-3.087; 13 3.575,-3.087; 14 4.225,-3.087; 15 4.225,3.087; 16 3.575,3.087; 17 2.925,3.087; 18 2.275,3.087; 19 1.625,3.087; 20 0.975,3.087; 21 0.325,3.087; 22 -0.325,3.087; 23 -0.975,3.087; 24 -1.625,3.087; 25 -2.275,3.087; 26 -2.925,3.087; 27 -3.575,3.087; 28 -4.225,3.087
smd 5 x 3: EXP 0,0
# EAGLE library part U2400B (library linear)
Charging of Batteries with Automatic Pre-Discharge Automatic recharging of NiCd / NiMH batteries. Source: http://www.elektronikpool.de/Sheets/U2400B.PDF

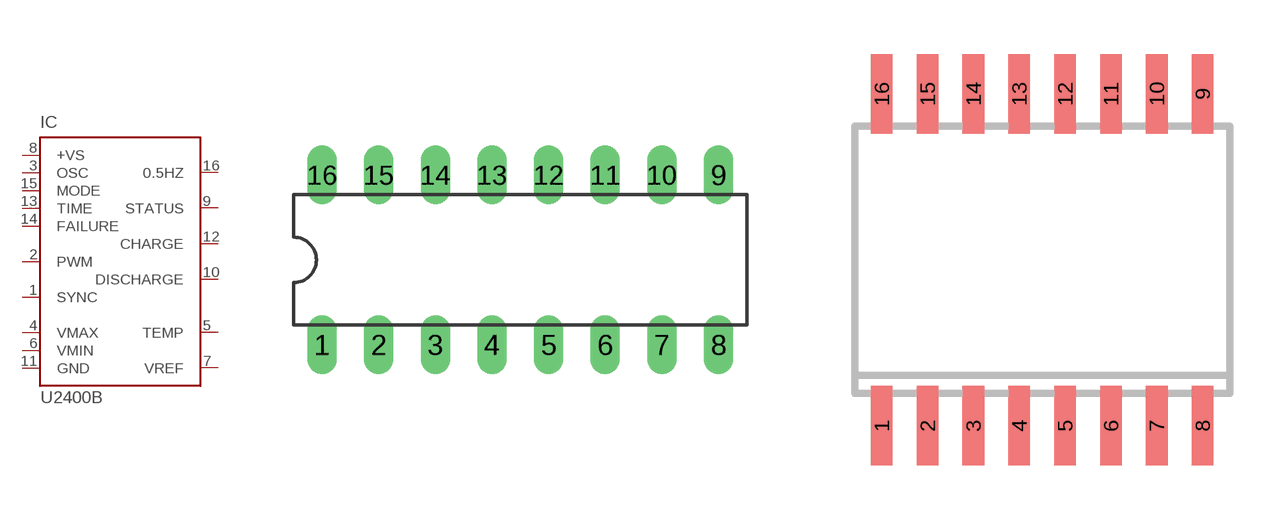
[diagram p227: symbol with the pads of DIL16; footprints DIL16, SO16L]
Designator prefix IC

## U2400B  [DIL16]
1  SYNC  in
2  PWM  in
3  OSC  in
4  VMAX  in
5  TEMP  in
6  VMIN  in
7  VREF  in
8  +VS  pwr
9  STATUS  out
10  DISCHARGE  out
11  GND  pwr
12  CHARGE  out
13  TIME  in
14  FAILURE  in
15  MODE  in
16  0.5HZ

## U2400B-FP  [SO16L]
Pads as for DIL16

## Footprint DIL16 (pad centres in mm)
Dual In Line Package
drill 0.813 long: 1 -8.89,-3.81; 2 -6.35,-3.81; 3 -3.81,-3.81; 4 -1.27,-3.81; 5 1.27,-3.81; 6 3.81,-3.81; 7 6.35,-3.81; 8 8.89,-3.81; 9 8.89,3.81; 10 6.35,3.81; 11 3.81,3.81; 12 1.27,3.81; 13 -1.27,3.81; 14 -3.81,3.81; 15 -6.35,3.81; 16 -8.89,3.81

## Footprint SO16L (pad centres in mm)
Small Outline Package 16 large
smd 0.6 x 2.2: 1 -4.445,-4.6; 2 -3.175,-4.6; 3 -1.905,-4.6; 4 -0.635,-4.6; 5 0.635,-4.6; 6 1.905,-4.6; 7 3.175,-4.6; 8 4.445,-4.6; 9 4.445,4.6; 10 3.175,4.6; 11 1.905,4.6; 12 0.635,4.6; 13 -0.635,4.6; 14 -1.905,4.6; 15 -3.175,4.6; 16 -4.445,4.6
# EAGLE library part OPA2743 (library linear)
12V, 7MHz, CMOS, Rail-to-Rail I/O Dual OP AMP Source: http://focus.ti.com/lit/ds/sbos201/sbos201.pdf

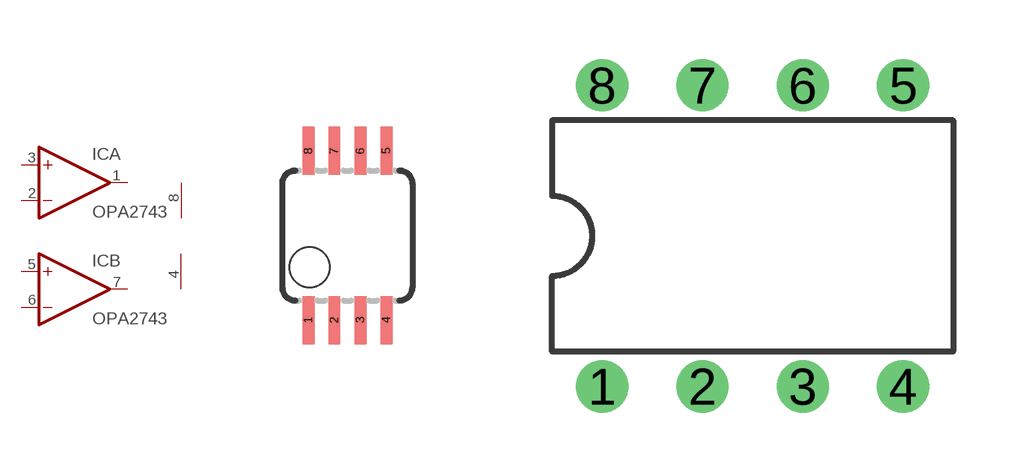
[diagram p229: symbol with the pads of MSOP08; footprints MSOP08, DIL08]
Designator prefix IC; gates A=OPAMP B=OPAMP P=PWR+-

## OPA2743EA  [MSOP08]
1  A:OUT  out
2  A:-IN  in
3  A:+IN  in
4  P:V-  pwr
5  B:+IN  in
6  B:-IN  in
7  B:OUT  out
8  P:V+  pwr

## OPA2743PA  [DIL08]
Pads as for MSOP08

## OPA2743UA  [SOIC8]
Pads as for MSOP08

## Footprint MSOP08 (pad centres in mm)
Mini Small Outline Package
smd 0.3 x 1.2: 1 -0.976,-2.113; 2 -0.326,-2.113; 3 0.324,-2.113; 4 0.974,-2.113; 5 0.974,2.112; 6 0.324,2.112; 7 -0.326,2.112; 8 -0.976,2.112

## Footprint DIL08 (pad centres in mm)
Dual In Line Package
drill 0.813 pad 1.27 round: 1 -3.81,-3.81; 2 -1.27,-3.81; 3 1.27,-3.81; 4 3.81,-3.81; 5 3.81,3.81; 6 1.27,3.81; 7 -1.27,3.81; 8 -3.81,3.81

## Footprint SOIC8 (pad centres in mm)
SOIC-8 CASE 751-07 Source: http://www.onsemi.com/pub/Collateral/MC34164-D.PDF D (R-PDSO-G8)PLATIC SMALL-OUTLINE PACKAGE Source: http://focus.ti.com/lit/ds/symlink/tlc27l2.pdf
smd 0.6 x 1.5: 1 -1.905,-2.75; 2 -0.635,-2.75; 3 0.635,-2.75; 4 1.905,-2.75; 5 1.905,2.75; 6 0.635,2.75; 7 -0.635,2.75; 8 -1.905,2.75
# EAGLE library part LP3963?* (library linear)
3A Fast Ultra Low Dropout Linear Regulator Source: http://cache.national.com/ds/LP/LP3963.pdf

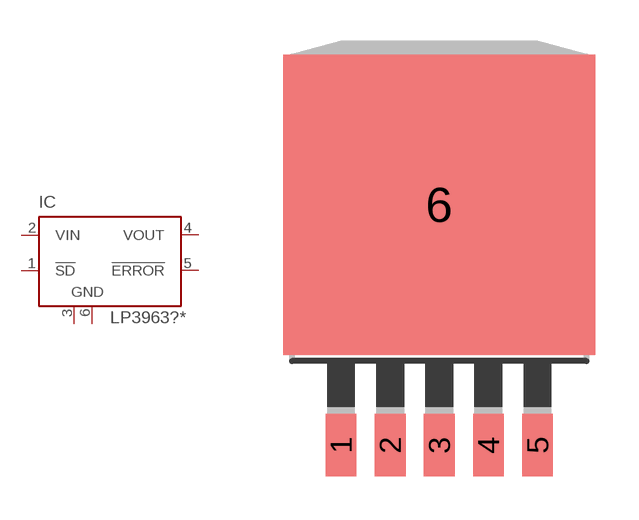
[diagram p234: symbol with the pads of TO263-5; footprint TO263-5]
Designator prefix IC

## LP3963ES-1.8, LP3963ES-2.5, LP3963ES-3.3, LP3963ES-5.0  [TO263-5]
1  !SD  in
2  VIN  in
3  GND  pwr
4  VOUT  in
5  !ERROR  out
6  GND  pwr

## Footprint TO263-5 (pad centres in mm)
TO-263
smd 1.067 x 2.159: 1 -3.404,-5.791; 2 -1.702,-5.791; 3 0,-5.791; 4 1.702,-5.791; 5 3.404,-5.791
smd 10.8 x 10.41: 6 0,2.54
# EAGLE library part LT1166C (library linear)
Power Output Stage Automatic Bias System Soource: http://www.linear.com

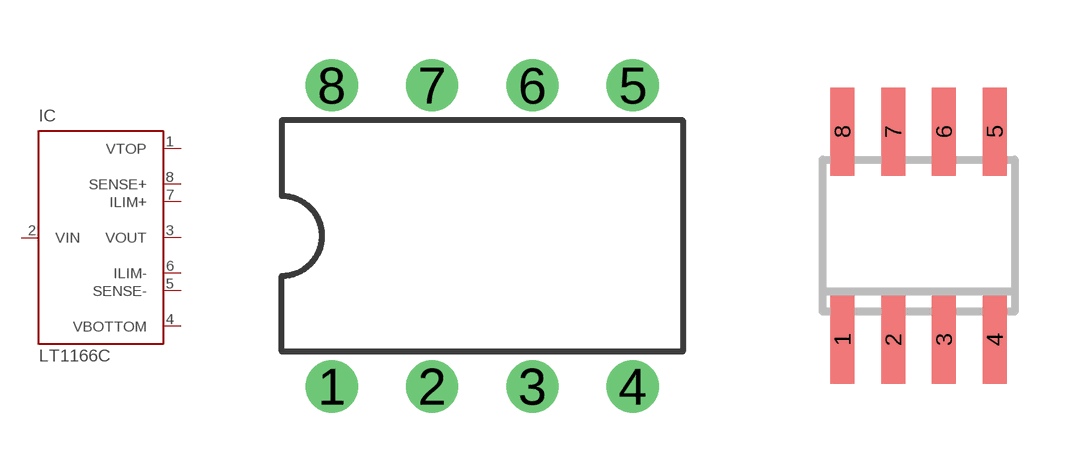
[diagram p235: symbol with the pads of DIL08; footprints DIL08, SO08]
Designator prefix IC

## LT1166CN8  [DIL08]
1  VTOP  in
2  VIN  in
3  VOUT  out
4  VBOTTOM  in
5  SENSE-  in
6  ILIM-  in
7  ILIM+  in
8  SENSE+  in

## LT1166CS8  [SO08]
Pads as for DIL08

## Footprint DIL08 (pad centres in mm)
Dual In Line Package
drill 0.813 pad 1.27 round: 1 -3.81,-3.81; 2 -1.27,-3.81; 3 1.27,-3.81; 4 3.81,-3.81; 5 3.81,3.81; 6 1.27,3.81; 7 -1.27,3.81; 8 -3.81,3.81

## Footprint SO08 (pad centres in mm)
Small Outline Package 8 NS Package M08A
smd 0.6 x 2.2: 1 -1.905,-2.6; 2 -0.635,-2.6; 3 0.635,-2.6; 4 1.905,-2.6; 5 1.905,2.6; 6 0.635,2.6; 7 -0.635,2.6; 8 -1.905,2.6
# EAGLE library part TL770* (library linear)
SUPPLY VOLTAGE SUPERVISORS TL7700A Series Source: http://www.st.com/stonline/products/literature/ds/1528.pdf

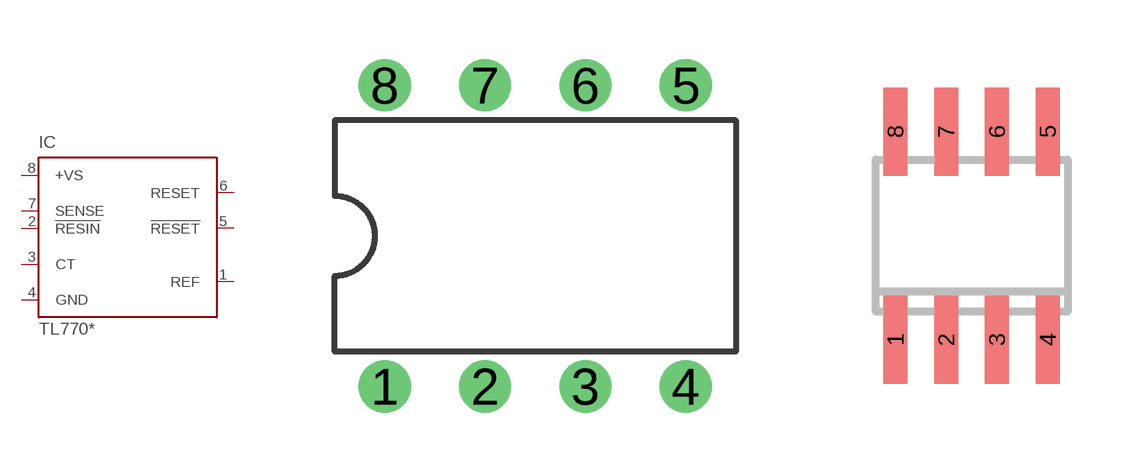
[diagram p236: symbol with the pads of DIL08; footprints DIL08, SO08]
Designator prefix IC

## TL77002ACP, TL77002AIP, TL77005ACP, TL77005AIP  [DIL08]
1  REF  in
2  !RESIN  in
3  CT  in
4  GND  pwr
5  !RESET  oc
6  RESET  oc
7  SENSE  in
8  +VS  in

## TL77002ACD, TL77002AID, TL77005ACD, TL77005AID  [SO08]
Pads as for DIL08

## Footprint DIL08 (pad centres in mm)
Dual In Line Package
drill 0.813 pad 1.27 round: 1 -3.81,-3.81; 2 -1.27,-3.81; 3 1.27,-3.81; 4 3.81,-3.81; 5 3.81,3.81; 6 1.27,3.81; 7 -1.27,3.81; 8 -3.81,3.81

## Footprint SO08 (pad centres in mm)
Small Outline Package 8 NS Package M08A
smd 0.6 x 2.2: 1 -1.905,-2.6; 2 -0.635,-2.6; 3 0.635,-2.6; 4 1.905,-2.6; 5 1.905,2.6; 6 0.635,2.6; 7 -0.635,2.6; 8 -1.905,2.6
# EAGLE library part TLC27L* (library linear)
LinCMOS(TM) PRECISION DUAL OPERATIONAL AMPLIFIERS Source: http://focus.ti.com/lit/ds/symlink/tlc27l2.pdf

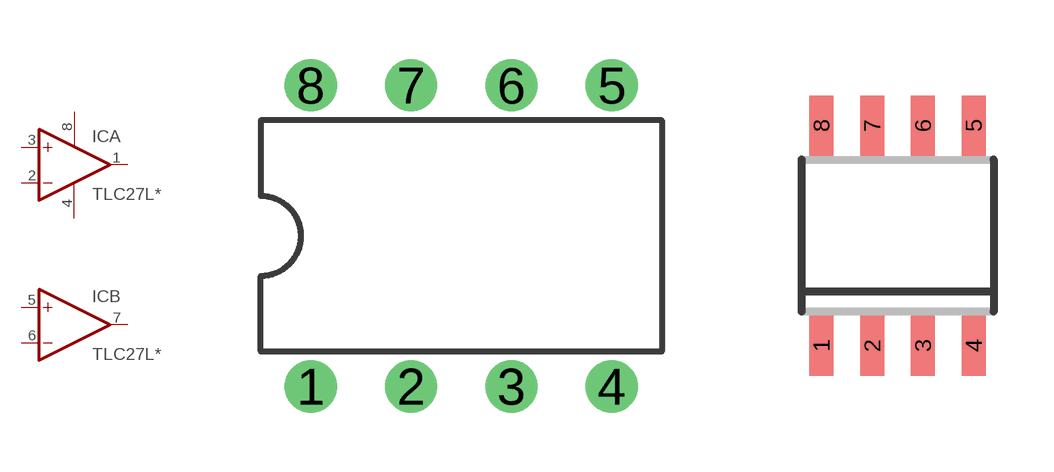
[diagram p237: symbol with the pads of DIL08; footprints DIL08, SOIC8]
Designator prefix IC; gates A=OPAMP B=OPAMP C=PWR-VDDGND

## TLC27L2ACP, TLC27L2AIP, TLC27L2BCP, TLC27L2BIP, TLC27L2CP, TLC27L2IP, TLC27L2MP, TLC27L7CP, TLC27L7IP, TLC27L7MP  [DIL08]
1  A:OUT  out
2  A:-IN  in
3  A:+IN  in
4  C:GND  pwr
5  B:+IN  in
6  B:-IN  in
7  B:OUT  out
8  C:VDD  pwr

## TLC27L2ACD, TLC27L2AID, TLC27L2BCD, TLC27L2BID, TLC27L2CD, TLC27L2ID, TLC27L2MD, TLC27L7CD, TLC27L7ID, TLC27L7MD  [SOIC8]
Pads as for DIL08

## TLC27L2MFK, TLC27L7MFK  [PLCC20S]
2  A:OUT  out
5  A:-IN  in
7  A:+IN  in
10  C:GND  pwr
12  B:+IN  in
15  B:-IN  in
17  B:OUT  out
20  C:VDD  pwr

## TLC27L2MJG, TLC27L7MJG  [DIL08]
Pads as for DIL08

## Footprint DIL08 (pad centres in mm)
Dual In Line Package
drill 0.813 pad 1.27 round: 1 -3.81,-3.81; 2 -1.27,-3.81; 3 1.27,-3.81; 4 3.81,-3.81; 5 3.81,3.81; 6 1.27,3.81; 7 -1.27,3.81; 8 -3.81,3.81

## Footprint SOIC8 (pad centres in mm)
SOIC-8 CASE 751-07 Source: http://www.onsemi.com/pub/Collateral/MC34164-D.PDF D (R-PDSO-G8)PLATIC SMALL-OUTLINE PACKAGE Source: http://focus.ti.com/lit/ds/symlink/tlc27l2.pdf
smd 0.6 x 1.5: 1 -1.905,-2.75; 2 -0.635,-2.75; 3 0.635,-2.75; 4 1.905,-2.75; 5 1.905,2.75; 6 0.635,2.75; 7 -0.635,2.75; 8 -1.905,2.75

## Footprint PLCC20S (pad centres in mm)
PLCC 20 lead square
smd 0.6 x 2.2: 1 0,4.3; 2 -1.27,4.3; 3 -2.54,4.3; 9 -2.54,-4.3; 10 -1.27,-4.3; 11 0,-4.3; 12 1.27,-4.3; 13 2.54,-4.3; 19 2.54,4.3; 20 1.27,4.3
smd 2.2 x 0.6: 4 -4.3,2.54; 5 -4.3,1.27; 6 -4.3,0; 7 -4.3,-1.27; 8 -4.3,-2.54; 14 4.3,-2.54; 15 4.3,-1.27; 16 4.3,0; 17 4.3,1.27; 18 4.3,2.54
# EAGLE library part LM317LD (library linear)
LOW CURRENT 1.2 TO 37V ADJUSTABLE VOLTAGE REGULATOR Source: http://pdf.alldatasheet.com

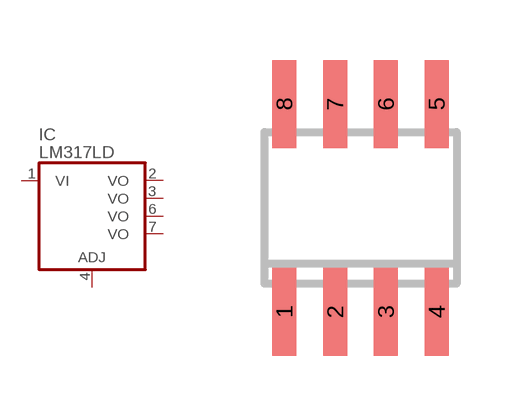
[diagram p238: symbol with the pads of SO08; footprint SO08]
Designator prefix IC

## LM317LD  [SO08]
1  VI  in
2  VO  pas
3  VO  pas
4  ADJ  in
6  VO  pas
7  VO  pas

## Footprint SO08 (pad centres in mm)
Small Outline Package 8 NS Package M08A
smd 0.6 x 2.2: 1 -1.905,-2.6; 2 -0.635,-2.6; 3 0.635,-2.6; 4 1.905,-2.6; 5 1.905,2.6; 6 0.635,2.6; 7 -0.635,2.6; 8 -1.905,2.6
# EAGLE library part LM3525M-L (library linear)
Single Port USB Power Switch and Over-Current Protection LOW active Source: http://cache.national.com/ds/LM/LM3525.pdf

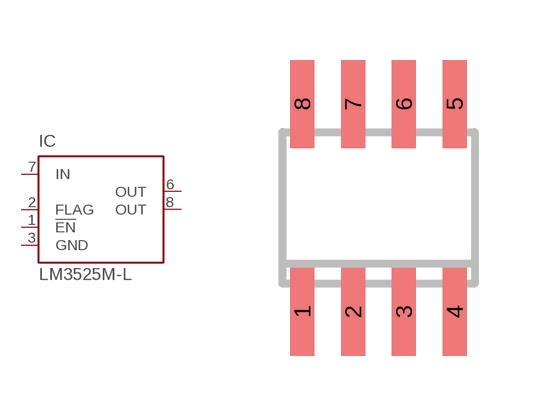
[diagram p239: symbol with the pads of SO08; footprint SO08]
Designator prefix IC

## LM3525M-L  [SO08]
1  !EN  in
2  FLAG  out
3  GND  pwr
4  NC  nc
5  NC  nc
6  OUT  out
7  IN  in
8  OUT  out

## Footprint SO08 (pad centres in mm)
Small Outline Package 8 NS Package M08A
smd 0.6 x 2.2: 1 -1.905,-2.6; 2 -0.635,-2.6; 3 0.635,-2.6; 4 1.905,-2.6; 5 1.905,2.6; 6 0.635,2.6; 7 -0.635,2.6; 8 -1.905,2.6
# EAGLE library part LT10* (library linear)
Low Noise, High Speed, Precision Operational Amplifiers Source: http://www.linear.com/pc/downloadDocument.do?navId=H0,C1,C1154,C1009,C1026,P1212,D2204

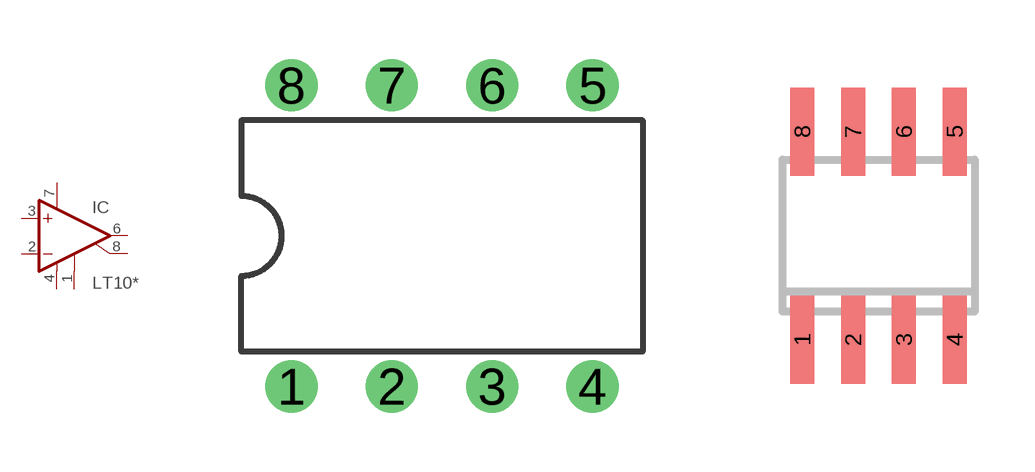
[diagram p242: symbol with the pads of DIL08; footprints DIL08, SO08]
Designator prefix IC

## LT1007ACN8, LT1007CN8, LT1007IN8, LT1037ACN8, LT1037CN8, LT1037IN8  [DIL08]
1  CMP1  pas
2  -IN  in
3  +IN  in
4  V-  pwr
6  OUT  out
7  V+  pwr
8  CMP2  pas

## LT1007CS8, LT1007IS8, LT1037CS8, LT1037IS8  [SO08]
Pads as for DIL08

## Footprint DIL08 (pad centres in mm)
Dual In Line Package
drill 0.813 pad 1.27 round: 1 -3.81,-3.81; 2 -1.27,-3.81; 3 1.27,-3.81; 4 3.81,-3.81; 5 3.81,3.81; 6 1.27,3.81; 7 -1.27,3.81; 8 -3.81,3.81

## Footprint SO08 (pad centres in mm)
Small Outline Package 8 NS Package M08A
smd 0.6 x 2.2: 1 -1.905,-2.6; 2 -0.635,-2.6; 3 0.635,-2.6; 4 1.905,-2.6; 5 1.905,2.6; 6 0.635,2.6; 7 -0.635,2.6; 8 -1.905,2.6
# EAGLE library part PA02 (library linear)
POWER OPERATIONAL AMPLIFIER SourcE: http://eportal.apexmicrotech.com/mainsite/pdf/pa02u.pdf

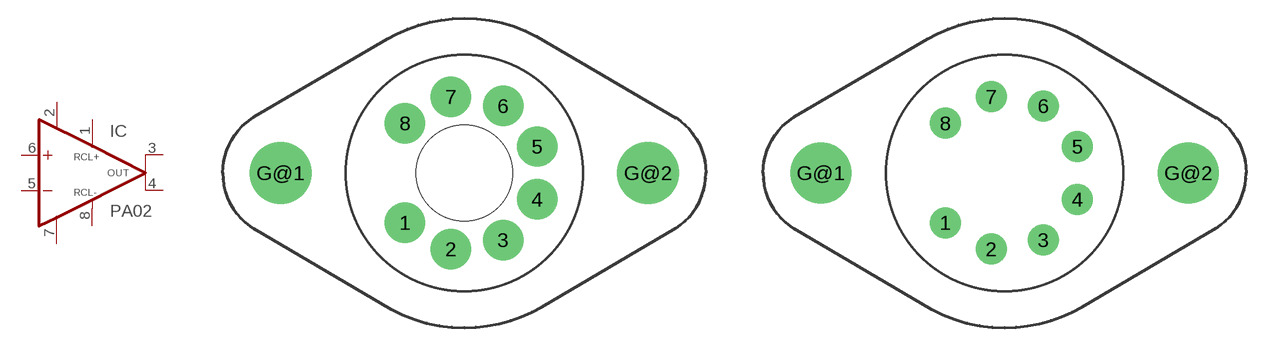
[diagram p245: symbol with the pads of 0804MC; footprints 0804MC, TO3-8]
Designator prefix IC

## PA02SOCKET  [0804MC]
1  RCL+  in
2  V+  pwr
3  OUT  out
4  OUT  out
5  -IN  in
6  +IN  in
7  V-  pwr
8  RCL-  in

## PA02  [TO3-8]
Pads as for 0804MC

## Footprint 0804MC (pad centres in mm)
TO3-8 Socket Source: http://focus.ti.com/lit/ds/symlink/0804mc.pdf
drill 2.3 pad 2.54 round: 1 -4.86,-4.08; 2 -1.1,-6.25; 3 3.18,-5.5; 4 5.97,-2.17; 5 5.97,2.17; 6 3.18,5.5; 7 -1.1,6.25; 8 -4.86,4.08
drill 4.064 pad 4.5 round: G@1 -15.07,0; G@2 15.07,0
hole 7.874 at 0,0

## Footprint TO3-8 (pad centres in mm)
8-PIN TO-3 Source: http://eportal.apexmicrotech.com/mainsite/pdf/CE.pdf
drill 1.2 pad 2.54 round: 1 -4.86,-4.08; 2 -1.1,-6.25; 3 3.18,-5.5; 4 5.97,-2.17; 5 5.97,2.17; 6 3.18,5.5; 7 -1.1,6.25; 8 -4.86,4.08
drill 4 pad 4.5 round: G@1 -15.07,0; G@2 15.07,0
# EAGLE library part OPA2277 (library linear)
High Precision OPERATIONAL AMPLIFIERS REPLACES OP-07, OP-77, OP-177 Source: opa277.pdf

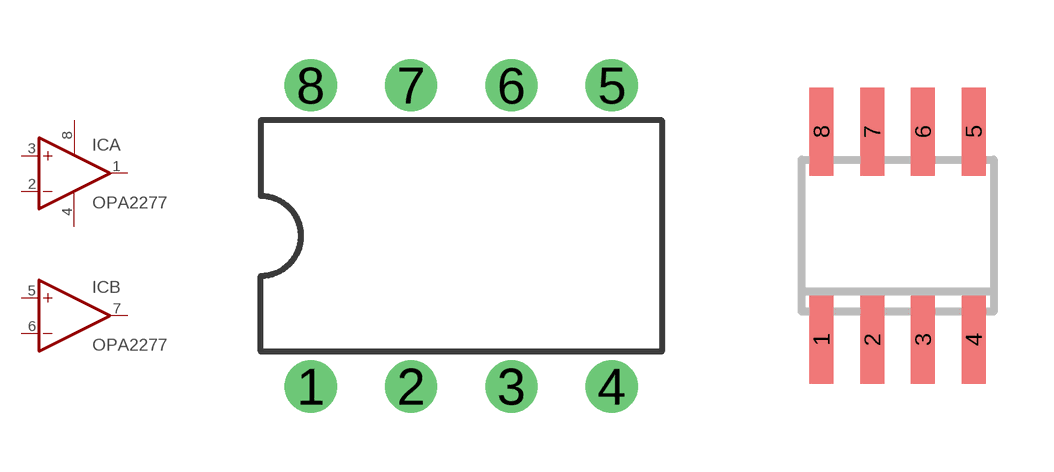
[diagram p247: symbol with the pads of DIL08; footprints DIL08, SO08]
Designator prefix IC; gates A=OPAMP B=OPAMP P=PWR+-

## OPA2277P  [DIL08]
1  A:OUT  out
2  A:-IN  in
3  A:+IN  in
4  P:V-  pwr
5  B:+IN  in
6  B:-IN  in
7  B:OUT  out
8  P:V+  pwr

## OPA2277U  [SO08]
Pads as for DIL08

## OPA2277AIDRM  [DFN8-4X4]
Pads as for DIL08

## Footprint DIL08 (pad centres in mm)
Dual In Line Package
drill 0.813 pad 1.27 round: 1 -3.81,-3.81; 2 -1.27,-3.81; 3 1.27,-3.81; 4 3.81,-3.81; 5 3.81,3.81; 6 1.27,3.81; 7 -1.27,3.81; 8 -3.81,3.81

## Footprint SO08 (pad centres in mm)
Small Outline Package 8 NS Package M08A
smd 0.6 x 2.2: 1 -1.905,-2.6; 2 -0.635,-2.6; 3 0.635,-2.6; 4 1.905,-2.6; 5 1.905,2.6; 6 0.635,2.6; 7 -0.635,2.6; 8 -1.905,2.6

## Footprint DFN8-4X4 (pad centres in mm)
DFN8 4x4 mm DRM (S-PDSO-N8) Source: opa277.pdf
smd 0.35 x 0.8: 1 -1.2,-1.975; 2 -0.4,-1.975; 3 0.4,-1.975; 4 1.2,-1.975; 5 1.2,1.975; 6 0.4,1.975; 7 -0.4,1.975; 8 -1.2,1.975
smd 3.38 x 2.45: TH 0,0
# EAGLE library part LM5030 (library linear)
100V Push-Pull Current Mode PWM Controller Source: http://cache.national.com/ds/LM/LM5030.pdf

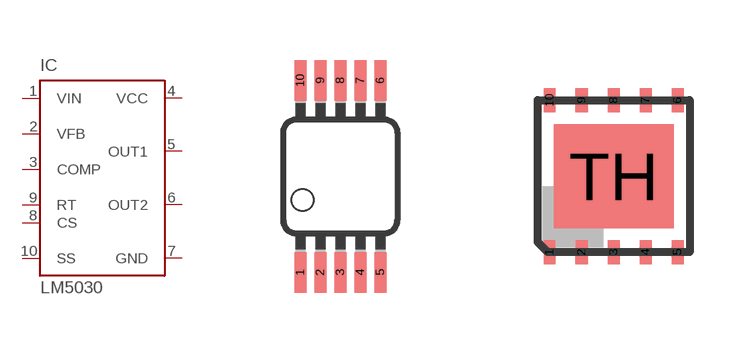
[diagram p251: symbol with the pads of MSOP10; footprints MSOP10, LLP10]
Designator prefix IC

## LM5030MM  [MSOP10]
1  VIN  in
2  VFB  in
3  COMP  out
4  VCC  pwr
5  OUT1  out
6  OUT2  out
7  GND  pwr
8  CS  pas
9  RT  in
10  SS  in

## LM5030SD  [LLP10]
Pads as for MSOP10

## Footprint MSOP10 (pad centres in mm)
10 Lead MSOP Package NS Package Number MUB10A Source: http://cache.national.com/ds/LM/LM5030.pdf
smd 0.3 x 1.02: 1 -1,-2.4; 2 -0.5,-2.4; 3 0,-2.4; 4 0.5,-2.4; 5 1,-2.4; 6 1,2.4; 7 0.5,2.4; 8 0,2.4; 9 -0.5,2.4; 10 -1,2.4

## Footprint LLP10 (pad centres in mm)
10 Lead LLP Package NS Package Number SDC10A Source: http://cache.national.com/ds/LM/LM5030.pdf
smd 0.3 x 0.61: 1 -1.6,-1.9; 2 -0.8,-1.9; 3 0,-1.9; 4 0.8,-1.9; 5 1.6,-1.9; 6 1.6,1.9; 7 0.8,1.9; 8 0,1.9; 9 -0.8,1.9; 10 -1.6,1.9
smd 3 x 2.6: TH 0,0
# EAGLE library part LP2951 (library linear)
100 mA, Low Power Low Dropout Voltage Regulator Source: http://www.onsemi.com/pub/Collateral/LP2950-D.PDF

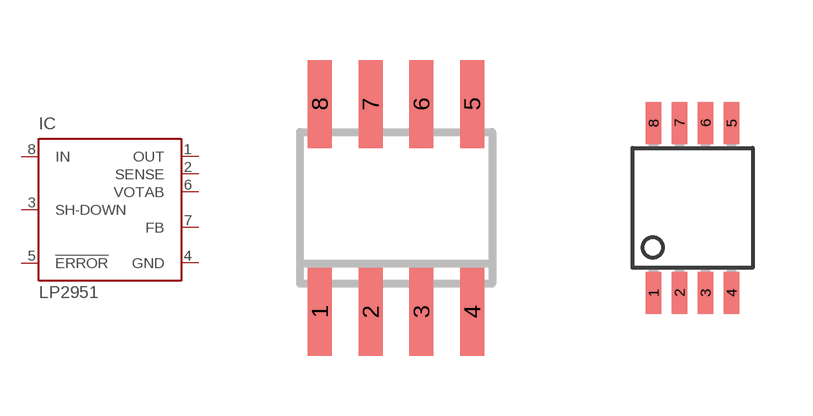
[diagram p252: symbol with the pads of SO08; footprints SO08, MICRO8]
Designator prefix IC

## LP2951D  [SO08]
1  OUT  in
2  SENSE  in
3  SH-DOWN  in
4  GND  pwr
5  !ERROR  out
6  VOTAB  pas
7  FB  in
8  IN  in

## LP2951DM  [MICRO8]
Pads as for SO08

## LP2951N  [DIL08]
Pads as for SO08

## Footprint SO08 (pad centres in mm)
Small Outline Package 8 NS Package M08A
smd 0.6 x 2.2: 1 -1.905,-2.6; 2 -0.635,-2.6; 3 0.635,-2.6; 4 1.905,-2.6; 5 1.905,2.6; 6 0.635,2.6; 7 -0.635,2.6; 8 -1.905,2.6

## Footprint MICRO8 (pad centres in mm)
Micro8 CASE 846A-02 Source: http://www.onsemi.com/pub/Collateral/MC34164-D.PDF
smd 0.38 x 1.05: 1 -0.975,-2.125; 2 -0.325,-2.125; 3 0.325,-2.125; 4 0.975,-2.125; 5 0.975,2.125; 6 0.325,2.125; 7 -0.325,2.125; 8 -0.975,2.125

## Footprint DIL08 (pad centres in mm)
Dual In Line Package
drill 0.813 pad 1.27 round: 1 -3.81,-3.81; 2 -1.27,-3.81; 3 1.27,-3.81; 4 3.81,-3.81; 5 3.81,3.81; 6 1.27,3.81; 7 -1.27,3.81; 8 -3.81,3.81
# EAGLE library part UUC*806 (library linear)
LOW-POWER, DUAL-OUTPUT, CURRENT-MODE PWM CONTROLLER BiCMOS Version of UC3846 Family Source: http://focus.ti.com/lit/ds/symlink/ucc3806.pdf

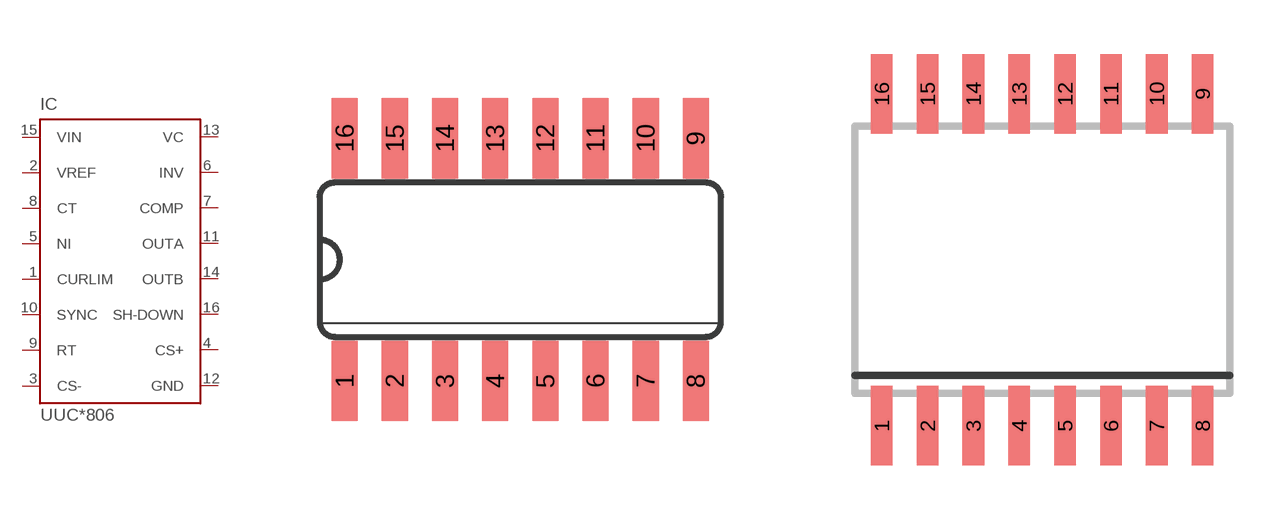
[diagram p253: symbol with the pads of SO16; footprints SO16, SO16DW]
Designator prefix IC

## UUC2806D  [SO16]
1  CURLIM  in
2  VREF  in
3  CS-  in
4  CS+  in
5  NI  in
6  INV  in
7  COMP  in
8  CT  in
9  RT  in
10  SYNC  in
11  OUTA  out
12  GND  pwr
13  VC  pwr
14  OUTB  out
15  VIN  in
16  SH-DOWN  in

## UUC2806DW, UUC3806DW  [SO16DW]
Pads as for SO16

## UUC1806J, UUC2806J, UUC3806J  [DIL16]
Pads as for SO16

## UUC2806P, UUC3806P  [DIL16]
Pads as for SO16

## UUC2806Q, UUC3806Q  [PLCC20S]
2  CURLIM  in
3  VREF  in
4  CS-  in
5  CS+  in
7  NI  in
8  INV  in
9  COMP  in
10  CT  in
12  RT  in
13  SYNC  in
14  OUTA  out
15  GND  pwr
17  VC  pwr
18  OUTB  out
19  VIN  in
20  SH-DOWN  in

## UUC2806M  [SSOP16]
Pads as for SO16

## UUC806PW  [TSSOP16]
Pads as for SO16

## Footprint SO16 (pad centres in mm)
Small Outline Package 16
smd 0.66 x 2.032: 1 -4.445,-3.073; 2 -3.175,-3.073; 3 -1.905,-3.073; 4 -0.635,-3.073; 5 0.635,-3.073; 6 1.905,-3.073; 7 3.175,-3.073; 8 4.445,-3.073; 9 4.445,3.073; 10 3.175,3.073; 11 1.905,3.073; 12 0.635,3.073; 13 -0.635,3.073; 14 -1.905,3.073; 15 -3.175,3.073; 16 -4.445,3.073

## Footprint SO16DW (pad centres in mm)
SOIC 16 DW SUFFIX PLASTIC SOIC PACKAGE CASE 751G-03 ISSUE B http://www.onsemi.com/pub/Collateral/MC14536B-D.PDF
smd 0.6 x 2.2: 1 -4.445,-4.6; 2 -3.175,-4.6; 3 -1.905,-4.6; 4 -0.635,-4.6; 5 0.635,-4.6; 6 1.905,-4.6; 7 3.175,-4.6; 8 4.445,-4.6; 9 4.445,4.6; 10 3.175,4.6; 11 1.905,4.6; 12 0.635,4.6; 13 -0.635,4.6; 14 -1.905,4.6; 15 -3.175,4.6; 16 -4.445,4.6

## Footprint DIL16 (pad centres in mm)
Dual In Line Package
drill 0.813 long: 1 -8.89,-3.81; 2 -6.35,-3.81; 3 -3.81,-3.81; 4 -1.27,-3.81; 5 1.27,-3.81; 6 3.81,-3.81; 7 6.35,-3.81; 8 8.89,-3.81; 9 8.89,3.81; 10 6.35,3.81; 11 3.81,3.81; 12 1.27,3.81; 13 -1.27,3.81; 14 -3.81,3.81; 15 -6.35,3.81; 16 -8.89,3.81

## Footprint PLCC20S (pad centres in mm)
PLCC 20 lead square
smd 0.6 x 2.2: 1 0,4.3; 2 -1.27,4.3; 3 -2.54,4.3; 9 -2.54,-4.3; 10 -1.27,-4.3; 11 0,-4.3; 12 1.27,-4.3; 13 2.54,-4.3; 19 2.54,4.3; 20 1.27,4.3
smd 2.2 x 0.6: 4 -4.3,2.54; 5 -4.3,1.27; 6 -4.3,0; 7 -4.3,-1.27; 8 -4.3,-2.54; 14 4.3,-2.54; 15 4.3,-1.27; 16 4.3,0; 17 4.3,1.27; 18 4.3,2.54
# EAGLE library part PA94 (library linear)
HIGH VOLTAGE POWER OPERATIONAL AMPLIFIER (900V) Source: www.apexmicrotech.com .. pa94u.pdf

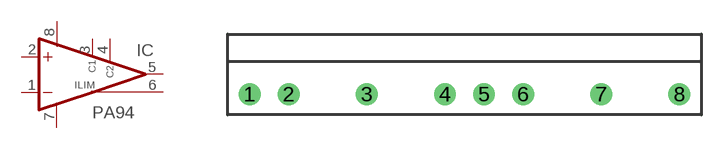
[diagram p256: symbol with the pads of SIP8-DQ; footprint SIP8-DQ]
Designator prefix IC

## PA94  [SIP8-DQ]
1  -IN  in
2  +IN  in
3  C1  pas
4  C2  pas
5  OUT  out
6  ILIM  in
7  V-  pwr
8  V+  pwr

## Footprint SIP8-DQ (pad centres in mm)
8 PIN SIP Style DQ Source: www.apexmicrotech.com .. DQ.pdf
drill 0.8 pad 1.422 round: 1 -13.97,0; 2 -11.43,0; 3 -6.35,0; 4 -1.27,0; 5 1.27,0; 6 3.81,0; 7 8.89,0; 8 13.97,0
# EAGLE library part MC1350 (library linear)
Monolitic IF Amplifier Source: MOTOROLA .. MC1350.pdf

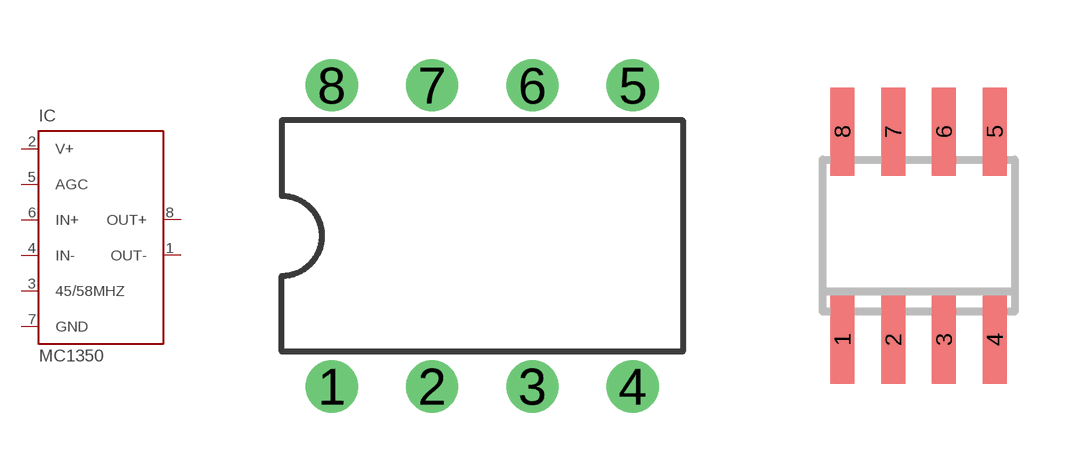
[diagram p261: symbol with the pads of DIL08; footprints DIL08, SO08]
Designator prefix IC

## MC1350P  [DIL08]
1  OUT-  in
2  V+  pwr
3  45/58MHZ  pas
4  IN-  in
5  AGC  in
6  IN+  in
7  GND  pwr
8  OUT+  in

## MC1350D  [SO08]
Pads as for DIL08

## Footprint DIL08 (pad centres in mm)
Dual In Line Package
drill 0.813 pad 1.27 round: 1 -3.81,-3.81; 2 -1.27,-3.81; 3 1.27,-3.81; 4 3.81,-3.81; 5 3.81,3.81; 6 1.27,3.81; 7 -1.27,3.81; 8 -3.81,3.81

## Footprint SO08 (pad centres in mm)
Small Outline Package 8 NS Package M08A
smd 0.6 x 2.2: 1 -1.905,-2.6; 2 -0.635,-2.6; 3 0.635,-2.6; 4 1.905,-2.6; 5 1.905,2.6; 6 0.635,2.6; 7 -0.635,2.6; 8 -1.905,2.6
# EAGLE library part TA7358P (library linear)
FM FRONT-END Source: TOSHIBA TA7358P.pdf

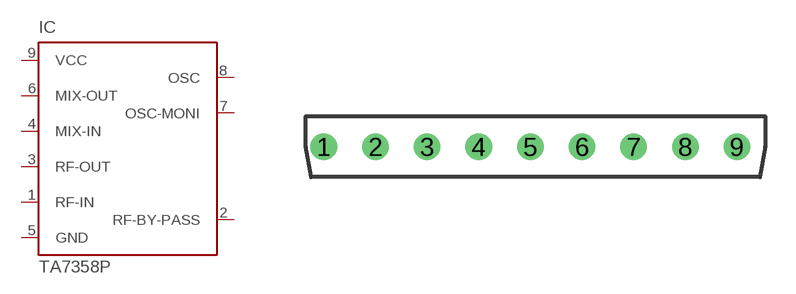
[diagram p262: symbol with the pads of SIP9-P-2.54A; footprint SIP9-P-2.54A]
Designator prefix IC

## TA7358P  [SIP9-P-2.54A]
1  RF-IN  in
2  RF-BY-PASS  in
3  RF-OUT  in
4  MIX-IN  in
5  GND  in
6  MIX-OUT  in
7  OSC-MONI  in
8  OSC  in
9  VCC  in

## Footprint SIP9-P-2.54A (pad centres in mm)
SIP9-P-2.54A Source: THOSHIBA .. TA7358P.pdf
drill 0.8 pad 1.27 round: 1 -10.16,0; 2 -7.62,0; 3 -5.08,0; 4 -2.54,0; 5 0,0; 6 2.54,0; 7 5.08,0; 8 7.62,0; 9 10.16,0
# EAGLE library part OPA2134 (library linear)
SoundPLUS (TM) High Performance AUDIO OPERATIONAL AMPLIFIERS Source: http://focus.ti.com/lit/ds/sbos058/sbos058.pdf

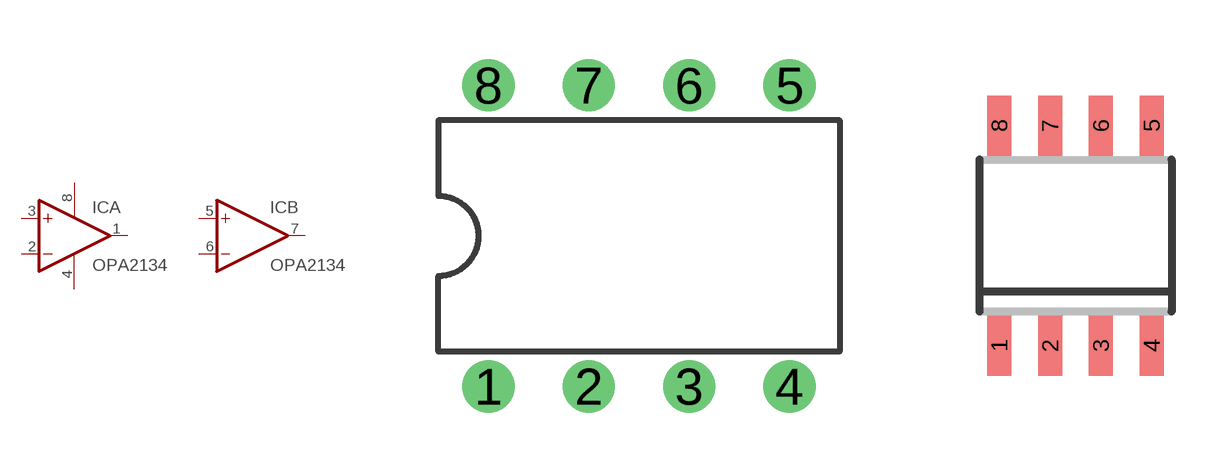
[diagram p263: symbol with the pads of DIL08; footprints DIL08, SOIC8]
Designator prefix IC; gates A=OPAMP B=OPAMP P=PWR+-

## OPA2134P  [DIL08]
1  A:OUT  out
2  A:-IN  in
3  A:+IN  in
4  P:V-  pwr
5  B:+IN  in
6  B:-IN  in
7  B:OUT  out
8  P:V+  pwr

## OPA2134D  [SOIC8]
Pads as for DIL08

## Footprint DIL08 (pad centres in mm)
Dual In Line Package
drill 0.813 pad 1.27 round: 1 -3.81,-3.81; 2 -1.27,-3.81; 3 1.27,-3.81; 4 3.81,-3.81; 5 3.81,3.81; 6 1.27,3.81; 7 -1.27,3.81; 8 -3.81,3.81

## Footprint SOIC8 (pad centres in mm)
SOIC-8 CASE 751-07 Source: http://www.onsemi.com/pub/Collateral/MC34164-D.PDF D (R-PDSO-G8)PLATIC SMALL-OUTLINE PACKAGE Source: http://focus.ti.com/lit/ds/symlink/tlc27l2.pdf
smd 0.6 x 1.5: 1 -1.905,-2.75; 2 -0.635,-2.75; 3 0.635,-2.75; 4 1.905,-2.75; 5 1.905,2.75; 6 0.635,2.75; 7 -0.635,2.75; 8 -1.905,2.75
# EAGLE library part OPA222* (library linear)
High Precision, Low Noise OPERATIONAL AMPLIFIERS Source: http://focus.ti.com/lit/ds/symlink/opa227.pdf

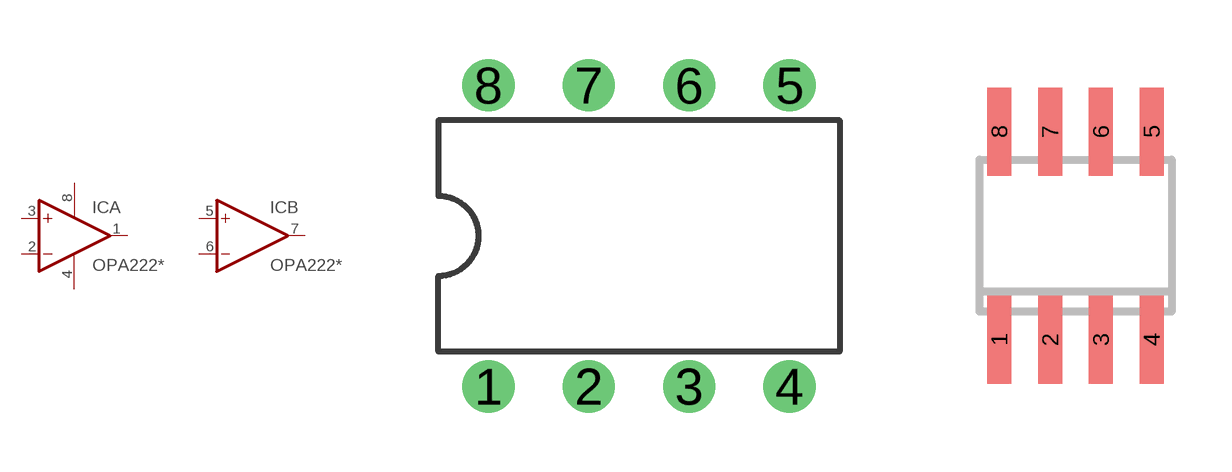
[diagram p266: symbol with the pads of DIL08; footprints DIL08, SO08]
Designator prefix IC; gates A=OPAMP B=OPAMP P=PWR+-

## OPA2227N, OPA2228N  [DIL08]
1  A:OUT  out
2  A:-IN  in
3  A:+IN  in
4  P:V-  pwr
5  B:+IN  in
6  B:-IN  in
7  B:OUT  out
8  P:V+  pwr

## OPA2227D, OPA2228D  [SO08]
Pads as for DIL08

## Footprint DIL08 (pad centres in mm)
Dual In Line Package
drill 0.813 pad 1.27 round: 1 -3.81,-3.81; 2 -1.27,-3.81; 3 1.27,-3.81; 4 3.81,-3.81; 5 3.81,3.81; 6 1.27,3.81; 7 -1.27,3.81; 8 -3.81,3.81

## Footprint SO08 (pad centres in mm)
Small Outline Package 8 NS Package M08A
smd 0.6 x 2.2: 1 -1.905,-2.6; 2 -0.635,-2.6; 3 0.635,-2.6; 4 1.905,-2.6; 5 1.905,2.6; 6 0.635,2.6; 7 -0.635,2.6; 8 -1.905,2.6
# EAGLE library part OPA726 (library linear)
Very Low Noise, High-Speed, 12V CMOS Operational Amplifier with Shutdown Source: http://focus.ti.com/lit/ds/symlink/opa725.pdf

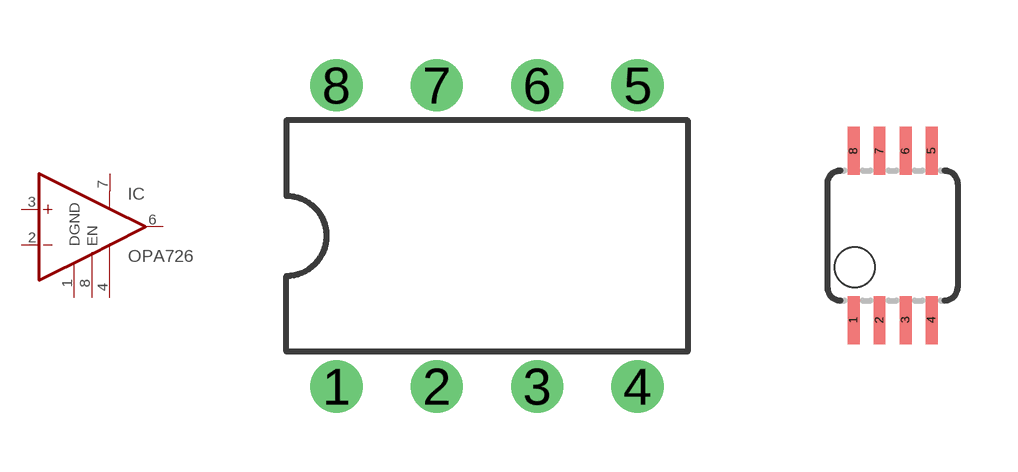
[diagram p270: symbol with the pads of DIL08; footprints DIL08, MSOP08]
Designator prefix IC

## OPA726P  [DIL08]
1  DGND  in
2  -IN  in
3  +IN  in
4  V-  pwr
6  OUT  out
7  V+  pwr
8  EN  in

## OPA726DGK  [MSOP08]
Pads as for DIL08

## Footprint DIL08 (pad centres in mm)
Dual In Line Package
drill 0.813 pad 1.27 round: 1 -3.81,-3.81; 2 -1.27,-3.81; 3 1.27,-3.81; 4 3.81,-3.81; 5 3.81,3.81; 6 1.27,3.81; 7 -1.27,3.81; 8 -3.81,3.81

## Footprint MSOP08 (pad centres in mm)
Mini Small Outline Package
smd 0.3 x 1.2: 1 -0.976,-2.113; 2 -0.326,-2.113; 3 0.324,-2.113; 4 0.974,-2.113; 5 0.974,2.112; 6 0.324,2.112; 7 -0.326,2.112; 8 -0.976,2.112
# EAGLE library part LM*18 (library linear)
FAST GENERAL-PURPOSE OPERATIONAL AMPLIFIER Sourde: http://focus.ti.com/lit/ds/slos063b/slos063b.pdf

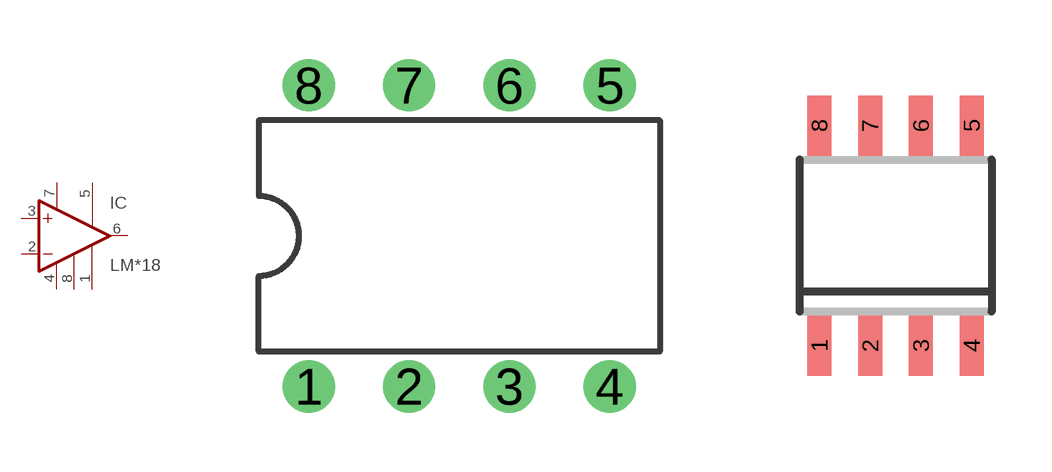
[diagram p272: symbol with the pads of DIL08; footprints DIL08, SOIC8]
Designator prefix IC

## LM318P  [DIL08]
1  BAL1  pas
2  -IN  in
3  +IN  in
4  V-  pwr
5  BAL2  pas
6  OUT  out
7  V+  pwr
8  COMP  pas

## LM318D  [SOIC8]
Pads as for DIL08

## LM318PS  [PS_R-PDSO-G8]
Pads as for DIL08

## LM118FK  [LCCC20]
2  BAL1  pas
5  -IN  in
7  +IN  in
10  V-  pwr
12  BAL2  pas
15  OUT  out
17  V+  pwr
20  COMP  pas

## Footprint DIL08 (pad centres in mm)
Dual In Line Package
drill 0.813 pad 1.27 round: 1 -3.81,-3.81; 2 -1.27,-3.81; 3 1.27,-3.81; 4 3.81,-3.81; 5 3.81,3.81; 6 1.27,3.81; 7 -1.27,3.81; 8 -3.81,3.81

## Footprint SOIC8 (pad centres in mm)
SOIC-8 CASE 751-07 Source: http://www.onsemi.com/pub/Collateral/MC34164-D.PDF D (R-PDSO-G8)PLATIC SMALL-OUTLINE PACKAGE Source: http://focus.ti.com/lit/ds/symlink/tlc27l2.pdf
smd 0.6 x 1.5: 1 -1.905,-2.75; 2 -0.635,-2.75; 3 0.635,-2.75; 4 1.905,-2.75; 5 1.905,2.75; 6 0.635,2.75; 7 -0.635,2.75; 8 -1.905,2.75

## Footprint PS_R-PDSO-G8 (pad centres in mm)
PS (R-PDSO-G8) Source: http://focus.ti.com/lit/ds/slos063b/slos063b.pdf
smd 0.6 x 1.5: 1 -1.905,-3.55; 2 -0.635,-3.55; 3 0.635,-3.55; 4 1.905,-3.55; 5 1.905,3.55; 6 0.635,3.55; 7 -0.635,3.55; 8 -1.905,3.55

## Footprint LCCC20 (pad centres in mm)
FK (S-CQCC-N20)</<LEADLEES CERAMIC CHIP CARRIER Source: http://focus.ti.com/lit/ds/slos063b/slos063b.pdf
smd 0.8 x 3.4: 1 0,3.8
smd 0.8 x 2: 2 -1.27,4.5; 3 -2.54,4.5; 9 -2.54,-4.5; 10 -1.27,-4.5; 11 0,-4.5; 12 1.27,-4.5; 13 2.54,-4.5; 19 2.54,4.5; 20 1.27,4.5
smd 2 x 0.8: 4 -4.5,2.54; 5 -4.5,1.27; 6 -4.5,0; 7 -4.5,-1.27; 8 -4.5,-2.54; 14 4.5,-2.54; 15 4.5,-1.27; 16 4.5,0; 17 4.5,1.27; 18 4.5,2.54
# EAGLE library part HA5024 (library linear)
Quad 125MHz Video Current Feedback Amplifier with Disable Source: http://www.intersil.com/data/fn/fn3550.pdf

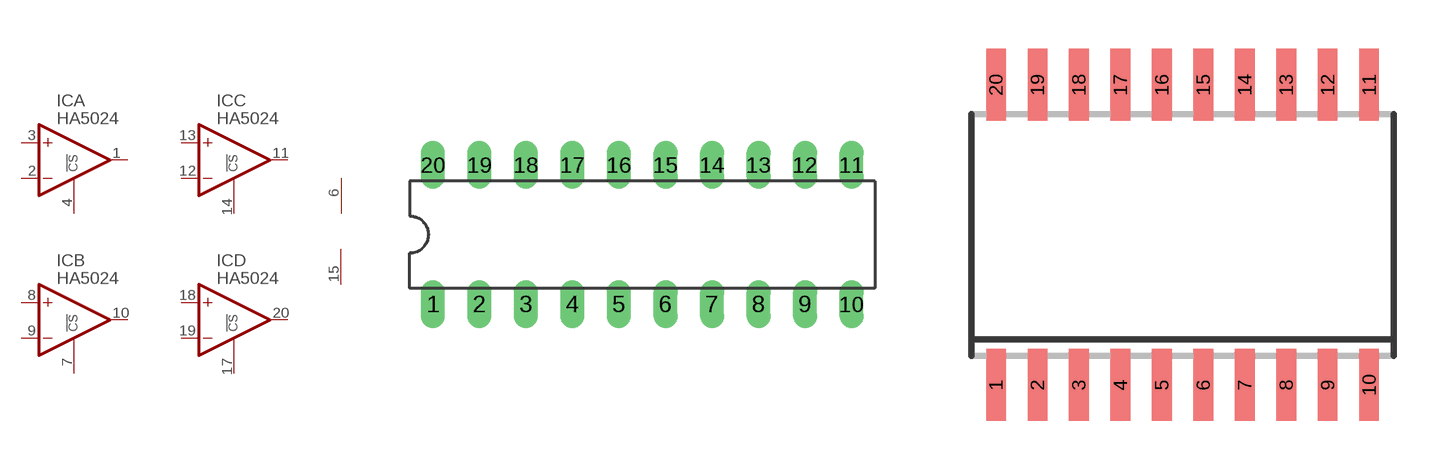
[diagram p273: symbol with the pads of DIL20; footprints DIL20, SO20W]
Designator prefix IC; gates A=OPAMP_CS B=OPAMP_CS C=OPAMP_CS D=OPAMP_CS P=PWR+-

## HA5024P  [DIL20]
1  A:OUT  out
2  A:-IN  in
3  A:+IN  in
4  A:!CS  in
6  P:V+  pwr
7  B:!CS  in
8  B:+IN  in
9  B:-IN  in
10  B:OUT  out
11  C:OUT  out
12  C:-IN  in
13  C:+IN  in
14  C:!CS  in
15  P:V-  pwr
17  D:!CS  in
18  D:+IN  in
19  D:-IN  in
20  D:OUT  out

## HA5024B  [SO20W]
Pads as for DIL20

## Footprint DIL20 (pad centres in mm)
Dual In Line Package
drill 0.813 long: 1 -11.43,-3.81; 2 -8.89,-3.81; 3 -6.35,-3.81; 4 -3.81,-3.81; 5 -1.27,-3.81; 6 1.27,-3.81; 7 3.81,-3.81; 8 6.35,-3.81; 9 8.89,-3.81; 10 11.43,-3.81; 11 11.43,3.81; 12 8.89,3.81; 13 6.35,3.81; 14 3.81,3.81; 15 1.27,3.81; 16 -1.27,3.81; 17 -3.81,3.81; 18 -6.35,3.81; 19 -8.89,3.81; 20 -11.43,3.81

## Footprint SO20W (pad centres in mm)
Small Outline Package 20 wide
smd 0.6 x 2.2: 1 -5.715,-4.6; 2 -4.445,-4.6; 3 -3.175,-4.6; 4 -1.905,-4.6; 5 -0.635,-4.6; 6 0.635,-4.6; 7 1.905,-4.6; 8 3.175,-4.6; 9 4.445,-4.6; 10 5.715,-4.6; 11 5.715,4.6; 12 4.445,4.6; 13 3.175,4.6; 14 1.905,4.6; 15 0.635,4.6; 16 -0.635,4.6; 17 -1.905,4.6; 18 -3.175,4.6; 19 -4.445,4.6; 20 -5.715,4.6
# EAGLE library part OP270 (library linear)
Dual Very Low Noise Precision Operational Amplifier Source: http://www.analog.com/static/imported-files/data_sheets/OP270.pdf

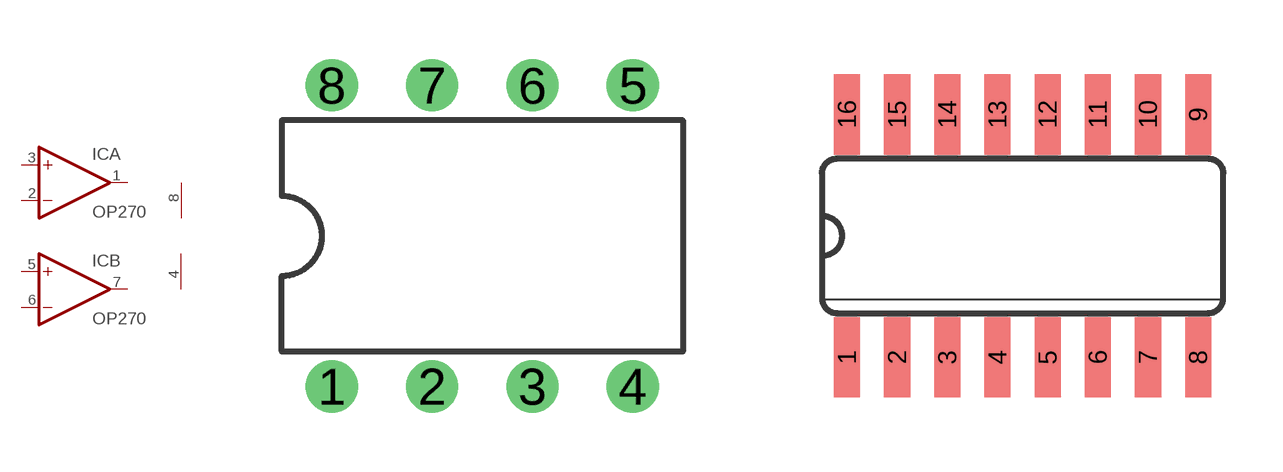
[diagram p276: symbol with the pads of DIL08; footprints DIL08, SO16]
Designator prefix IC; gates A=OPAMP B=OPAMP P=PWR+-

## OP270P  [DIL08]
1  A:OUT  out
2  A:-IN  in
3  A:+IN  in
4  P:V-  pwr
5  B:+IN  in
6  B:-IN  in
7  B:OUT  out
8  P:V+  pwr

## OP270S  [SO16]
1  A:-IN  in
2  A:+IN  in
4  P:V-  pwr
6  B:+IN  in
7  B:-IN  in
10  B:OUT  out
13  P:V+  pwr
16  A:OUT  out

## Footprint DIL08 (pad centres in mm)
Dual In Line Package
drill 0.813 pad 1.27 round: 1 -3.81,-3.81; 2 -1.27,-3.81; 3 1.27,-3.81; 4 3.81,-3.81; 5 3.81,3.81; 6 1.27,3.81; 7 -1.27,3.81; 8 -3.81,3.81

## Footprint SO16 (pad centres in mm)
Small Outline Package 16
smd 0.66 x 2.032: 1 -4.445,-3.073; 2 -3.175,-3.073; 3 -1.905,-3.073; 4 -0.635,-3.073; 5 0.635,-3.073; 6 1.905,-3.073; 7 3.175,-3.073; 8 4.445,-3.073; 9 4.445,3.073; 10 3.175,3.073; 11 1.905,3.073; 12 0.635,3.073; 13 -0.635,3.073; 14 -1.905,3.073; 15 -3.175,3.073; 16 -4.445,3.073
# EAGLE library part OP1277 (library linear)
Precision Low Noise, Low Input Bias Current Operational Amplifiers Source: OP1177_2177_4177.pdf

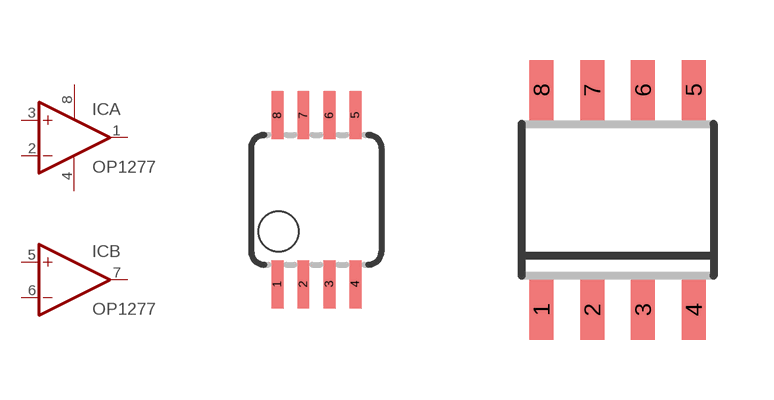
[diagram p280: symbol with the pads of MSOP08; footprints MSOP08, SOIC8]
Designator prefix IC; gates A=OPAMP B=OPAMP P=PWR+-

## OP1277RM  [MSOP08]
1  A:OUT  out
2  A:-IN  in
3  A:+IN  in
4  P:V-  pwr
5  B:+IN  in
6  B:-IN  in
7  B:OUT  out
8  P:V+  pwr

## OP1277R  [SOIC8]
Pads as for MSOP08

## Footprint MSOP08 (pad centres in mm)
Mini Small Outline Package
smd 0.3 x 1.2: 1 -0.976,-2.113; 2 -0.326,-2.113; 3 0.324,-2.113; 4 0.974,-2.113; 5 0.974,2.112; 6 0.324,2.112; 7 -0.326,2.112; 8 -0.976,2.112

## Footprint SOIC8 (pad centres in mm)
SOIC-8 CASE 751-07 Source: http://www.onsemi.com/pub/Collateral/MC34164-D.PDF D (R-PDSO-G8)PLATIC SMALL-OUTLINE PACKAGE Source: http://focus.ti.com/lit/ds/symlink/tlc27l2.pdf
smd 0.6 x 1.5: 1 -1.905,-2.75; 2 -0.635,-2.75; 3 0.635,-2.75; 4 1.905,-2.75; 5 1.905,2.75; 6 0.635,2.75; 7 -0.635,2.75; 8 -1.905,2.75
